// Mitsubishi GX Works2 project: PJT07_14_PLC(20220517_01)   PLC: Q03UDV

FUNCTION_BLOCK Alarm_FB
VAR_INPUT
  IB_Alarm : BOOL;  (* 入力@警報発生(0:-/1:発生) *)
END_VAR
VAR
  VT_AlarmDelayTimer : TIMER;  (* 内部@異常入力ﾃﾞｨﾚｲﾀｲﾏ *)
END_VAR
VAR_INPUT
  IW_DelayTimerVal : INT;  (* 入力@ﾃﾞｨﾚｲﾀｲﾏ値 *)
END_VAR
VAR_OUTPUT
  OB_AlarmHolding : BOOL;  (* 出力@ｱﾗｰﾑ自己保持(0:-/1:保持) *)
END_VAR
VAR_INPUT
  IB_AlarmResetPB : BOOL;  (* 入力@警報ﾘｾｯﾄPB(0:-/1:ﾘｾｯﾄ) *)
END_VAR
VAR
  VT_BuzzerStopTimer : TIMER;  (* 内部@ﾌﾞｻﾞｰｽﾄｯﾌﾟﾀｲﾏ *)
END_VAR
VAR_INPUT
  IW_BzStopTVal : INT;  (* 入力@ﾌﾞｻﾞｰｽﾄｯﾌﾟﾀｲﾏ値 *)
END_VAR
VAR
  VB_BuzzerStopFLG : BOOL;  (* 内部@ﾌﾞｻﾞｰｽﾄｯﾌﾟﾃﾞﾊﾞｲｽ(0:-/1:停止) *)
END_VAR
VAR_OUTPUT
  OB_DisplayFLG : BOOL;  (* 出力@ｱﾗｰﾑ表示ﾃﾞﾊﾞｲｽ(0:点滅/1:点灯) *)
END_VAR
VAR_INPUT
  IB_BuzzerStopPB : BOOL;  (* 入力@ﾌﾞｻﾞｰｽﾄｯﾌﾟPB(0:-/1:ｽﾄｯﾌﾟ) *)
END_VAR
VAR_OUTPUT
  OB_BuzzerFLG : BOOL;  (* 出力@ﾌﾞｻﾞｰﾌﾗｸﾞ *)
END_VAR
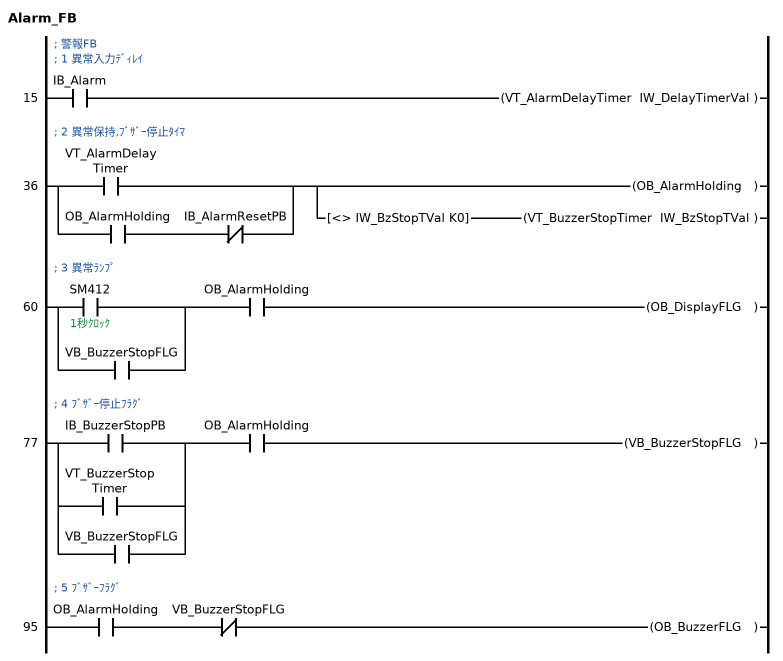
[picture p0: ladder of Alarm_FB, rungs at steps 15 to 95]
; 警報FB
; 1 異常入力ﾃﾞｨﾚｲ
15    LD      IB_Alarm
      OUT     VT_AlarmDelayTimer IW_DelayTimerVal
; 2 異常保持,ﾌﾞｻﾞｰ停止ﾀｲﾏ
36    LD      VT_AlarmDelayTimer
      LD      OB_AlarmHolding
      ANI     IB_AlarmResetPB
      ORB
      OUT     OB_AlarmHolding
      AND<>   IW_BzStopTVal K0
      OUT     VT_BuzzerStopTimer IW_BzStopTVal
; 3 異常ﾗﾝﾌﾟ
60    LD      SM412  ; 1秒ｸﾛｯｸ
      OR      VB_BuzzerStopFLG
      AND     OB_AlarmHolding
      OUT     OB_DisplayFLG
; 4 ﾌﾞｻﾞｰ停止ﾌﾗｸﾞ
77    LD      IB_BuzzerStopPB
      OR      VT_BuzzerStopTimer
      OR      VB_BuzzerStopFLG
      AND     OB_AlarmHolding
      OUT     VB_BuzzerStopFLG
; 5 ﾌﾞｻﾞｰﾌﾗｸﾞ
95    LD      OB_AlarmHolding
      ANI     VB_BuzzerStopFLG
      OUT     OB_BuzzerFLG
END_FUNCTION_BLOCK

PROGRAM 11_Alarm
VAR
  Alarm_FB_1 : Alarm_FB;
  Alarm_FB_2 : Alarm_FB;
END_VAR
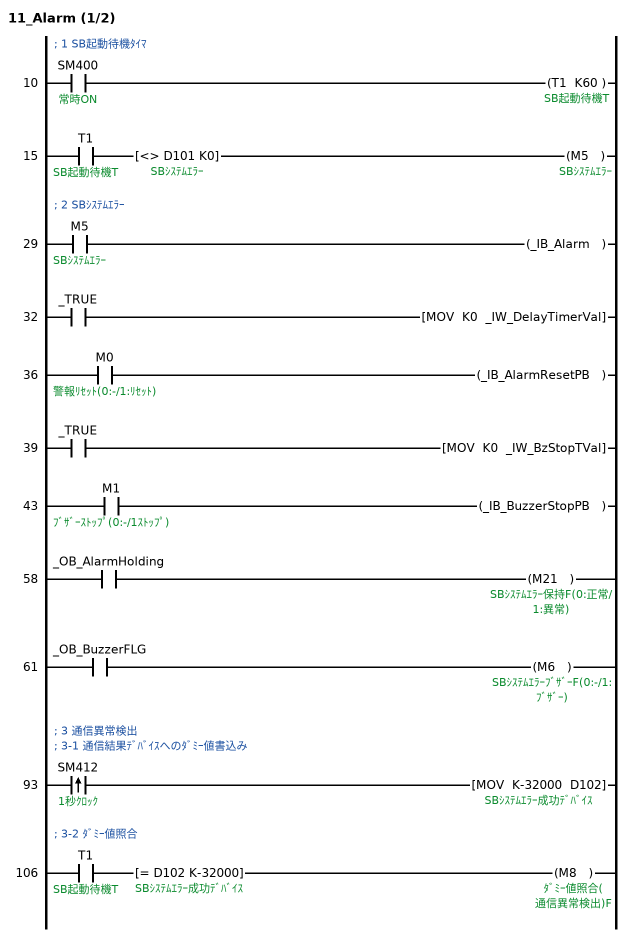
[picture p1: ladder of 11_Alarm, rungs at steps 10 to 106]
; 1 SB起動待機ﾀｲﾏ
10    LD      SM400  ; 常時ON
      OUT     T1 K60  ; SB起動待機T
15    LD      T1  ; SB起動待機T
      AND<>   D101 K0  ; SBｼｽﾃﾑｴﾗｰ
      OUT     M5  ; SBｼｽﾃﾑｴﾗｰ
; FB BLK START Alarm_FB(Alarm_FB_1)
; 2 SBｼｽﾃﾑｴﾗｰ
29    LD      M5  ; SBｼｽﾃﾑｴﾗｰ
      OUT     _IB_Alarm
32    LD      _TRUE
      MOV     K0 _IW_DelayTimerVal
36    LD      M0  ; 警報ﾘｾｯﾄ(0:-/1:ﾘｾｯﾄ)
      OUT     _IB_AlarmResetPB
39    LD      _TRUE
      MOV     K0 _IW_BzStopTVal
43    LD      M1  ; ﾌﾞｻﾞｰｽﾄｯﾌﾟ(0:-/1ｽﾄｯﾌﾟ)
      OUT     _IB_BuzzerStopPB
; FB START
; FB_NAME Alarm_FB
; INSTANCE_NAME Alarm_FB_1
; FB IN_B:IB_Alarm
; FB OUT_OB_AlarmHolding:B
; FB IN_W:IW_DelayTimerVal
; FB OUT_OB_DisplayFLG:B
; FB IN_B:IB_AlarmResetPB
; FB OUT_OB_BuzzerFLG:B
; FB IN_W:IW_BzStopTVal
; FB IN_B:IB_BuzzerStopPB
; FB END
58    LD      _OB_AlarmHolding
      OUT     M21  ; SBｼｽﾃﾑｴﾗｰ保持F(0:正常/1:異常)
61    LD      _OB_BuzzerFLG
      OUT     M6  ; SBｼｽﾃﾑｴﾗｰﾌﾞｻﾞｰF(0:-/1:ﾌﾞｻﾞｰ)
; FB BLK END
; 3 通信異常検出
; 3-1 通信結果ﾃﾞﾊﾞｲｽへのﾀﾞﾐｰ値書込み
93    LDP     SM412  ; 1秒ｸﾛｯｸ
      MOV     K-32000 D102  ; SBｼｽﾃﾑｴﾗｰ成功ﾃﾞﾊﾞｲｽ
; 3-2 ﾀﾞﾐｰ値照合
106   LD      T1  ; SB起動待機T
      AND=    D102 K-32000  ; SBｼｽﾃﾑｴﾗｰ成功ﾃﾞﾊﾞｲｽ
      OUT     M8  ; ﾀﾞﾐｰ値照合(通信異常検出)F
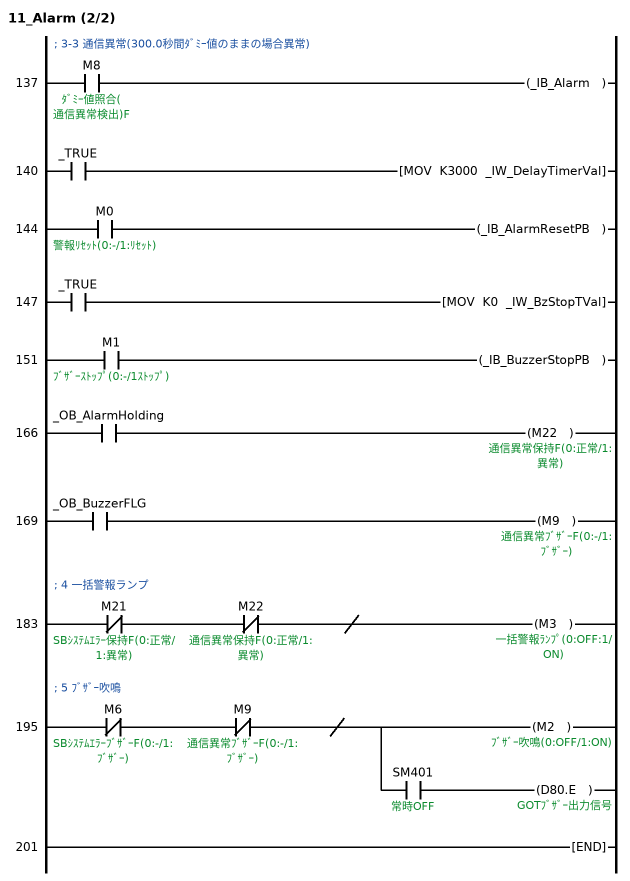
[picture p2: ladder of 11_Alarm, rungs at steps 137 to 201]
; FB BLK START Alarm_FB(Alarm_FB_2)
; 3-3 通信異常(300.0秒間ﾀﾞﾐｰ値のままの場合異常)
137   LD      M8  ; ﾀﾞﾐｰ値照合(通信異常検出)F
      OUT     _IB_Alarm
140   LD      _TRUE
      MOV     K3000 _IW_DelayTimerVal
144   LD      M0  ; 警報ﾘｾｯﾄ(0:-/1:ﾘｾｯﾄ)
      OUT     _IB_AlarmResetPB
147   LD      _TRUE
      MOV     K0 _IW_BzStopTVal
151   LD      M1  ; ﾌﾞｻﾞｰｽﾄｯﾌﾟ(0:-/1ｽﾄｯﾌﾟ)
      OUT     _IB_BuzzerStopPB
; FB START
; FB_NAME Alarm_FB
; INSTANCE_NAME Alarm_FB_2
; FB IN_B:IB_Alarm
; FB OUT_OB_AlarmHolding:B
; FB IN_W:IW_DelayTimerVal
; FB OUT_OB_DisplayFLG:B
; FB IN_B:IB_AlarmResetPB
; FB OUT_OB_BuzzerFLG:B
; FB IN_W:IW_BzStopTVal
; FB IN_B:IB_BuzzerStopPB
; FB END
166   LD      _OB_AlarmHolding
      OUT     M22  ; 通信異常保持F(0:正常/1:異常)
169   LD      _OB_BuzzerFLG
      OUT     M9  ; 通信異常ﾌﾞｻﾞｰF(0:-/1:ﾌﾞｻﾞｰ)
; FB BLK END
; 4 一括警報ランプ
183   LDI     M21  ; SBｼｽﾃﾑｴﾗｰ保持F(0:正常/1:異常)
      ANI     M22  ; 通信異常保持F(0:正常/1:異常)
      INV
      OUT     M3  ; 一括警報ﾗﾝﾌﾟ(0:OFF:1/ON)
; 5 ﾌﾞｻﾞｰ吹鳴
195   LDI     M6  ; SBｼｽﾃﾑｴﾗｰﾌﾞｻﾞｰF(0:-/1:ﾌﾞｻﾞｰ)
      ANI     M9  ; 通信異常ﾌﾞｻﾞｰF(0:-/1:ﾌﾞｻﾞｰ)
      INV
      OUT     M2  ; ﾌﾞｻﾞｰ吹鳴(0:OFF/1:ON)
      AND     SM401  ; 常時OFF
      OUT     D80.E  ; GOTﾌﾞｻﾞｰ出力信号
201   END
END_PROGRAM

PROGRAM 02_#2  // SB_Initial
VAR
  __IST_553ac48fffaf4984 : I+ST_553ac48fffaf4984;
END_VAR
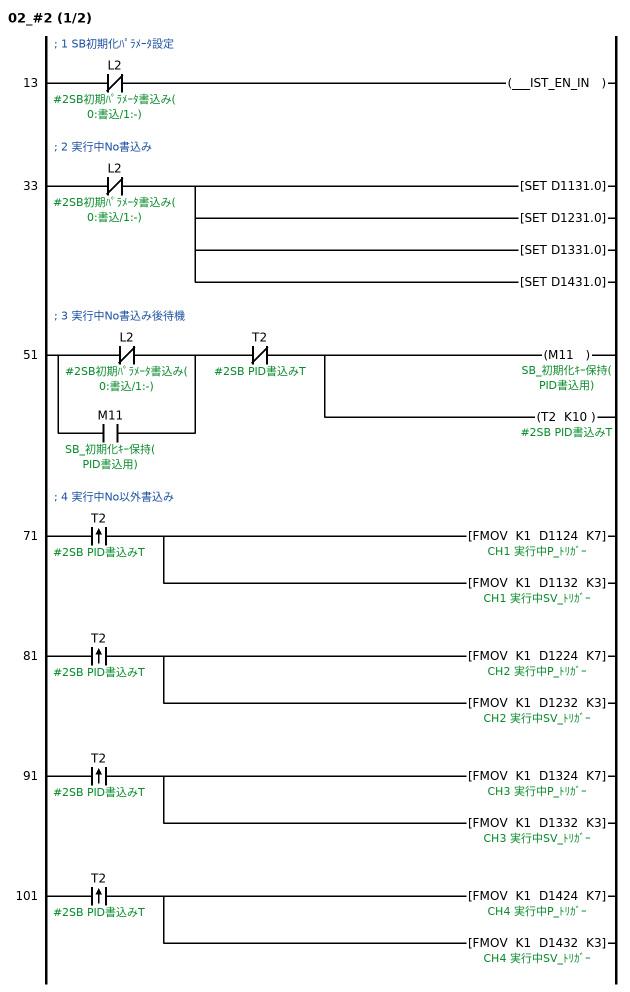
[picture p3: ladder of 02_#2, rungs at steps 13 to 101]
; FB BLK START I+ST_553ac48fffaf4984(__IST_553ac48fffaf4984)
; 1 SB初期化ﾊﾟﾗﾒｰﾀ設定
13    LDI     L2  ; #2SB初期ﾊﾟﾗﾒｰﾀ書込み(0:書込/1:-)
      OUT     ___IST_EN_IN
; FB START
; FB_NAME I+ST_553ac48fffaf4984
; INSTANCE_NAME __IST_553ac48fffaf4984
; FB IN_B:__IST_EN_IN
; FB OUT___IST_EN_OUT:B
; FB END
; FB BLK END
; 2 実行中No書込み
33    LDI     L2  ; #2SB初期ﾊﾟﾗﾒｰﾀ書込み(0:書込/1:-)
      SET     D1131.0
      SET     D1231.0
      SET     D1331.0
      SET     D1431.0
; 3 実行中No書込み後待機
51    LDI     L2  ; #2SB初期ﾊﾟﾗﾒｰﾀ書込み(0:書込/1:-)
      OR      M11  ; SB_初期化ｷｰ保持(PID書込用)
      ANI     T2  ; #2SB PID書込みT
      OUT     M11  ; SB_初期化ｷｰ保持(PID書込用)
      OUT     T2 K10  ; #2SB PID書込みT
; 4 実行中No以外書込み
71    LDP     T2  ; #2SB PID書込みT
      FMOV    K1 D1124 K7  ; CH1 実行中P_ﾄﾘｶﾞｰ
      FMOV    K1 D1132 K3  ; CH1 実行中SV_ﾄﾘｶﾞｰ
81    LDP     T2  ; #2SB PID書込みT
      FMOV    K1 D1224 K7  ; CH2 実行中P_ﾄﾘｶﾞｰ
      FMOV    K1 D1232 K3  ; CH2 実行中SV_ﾄﾘｶﾞｰ
91    LDP     T2  ; #2SB PID書込みT
      FMOV    K1 D1324 K7  ; CH3 実行中P_ﾄﾘｶﾞｰ
      FMOV    K1 D1332 K3  ; CH3 実行中SV_ﾄﾘｶﾞｰ
101   LDP     T2  ; #2SB PID書込みT
      FMOV    K1 D1424 K7  ; CH4 実行中P_ﾄﾘｶﾞｰ
      FMOV    K1 D1432 K3  ; CH4 実行中SV_ﾄﾘｶﾞｰ
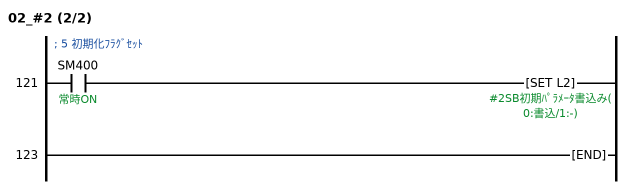
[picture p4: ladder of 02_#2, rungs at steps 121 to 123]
; 5 初期化ﾌﾗｸﾞｾｯﾄ
121   LD      SM400  ; 常時ON
      SET     L2  ; #2SB初期ﾊﾟﾗﾒｰﾀ書込み(0:書込/1:-)
123   END
END_PROGRAM

PROGRAM 22_#2  // SB100
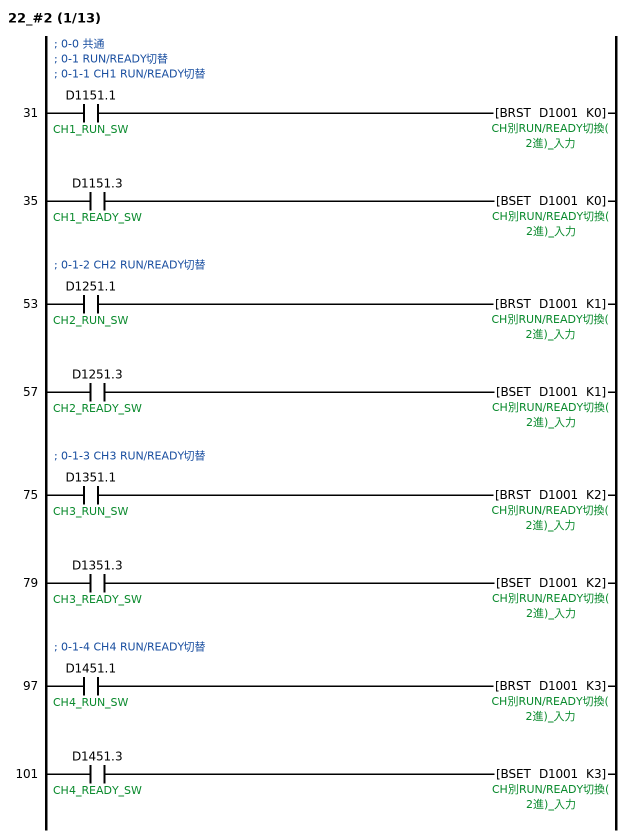
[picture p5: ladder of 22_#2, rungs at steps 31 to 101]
; 0-0 共通
; 0-1 RUN/READY切替
; 0-1-1 CH1 RUN/READY切替
31    LD      D1151.1  ; CH1_RUN_SW
      BRST    D1001 K0  ; CH別RUN/READY切換(2進)_入力
35    LD      D1151.3  ; CH1_READY_SW
      BSET    D1001 K0
; 0-1-2 CH2 RUN/READY切替
53    LD      D1251.1  ; CH2_RUN_SW
      BRST    D1001 K1
57    LD      D1251.3  ; CH2_READY_SW
      BSET    D1001 K1
; 0-1-3 CH3 RUN/READY切替
75    LD      D1351.1  ; CH3_RUN_SW
      BRST    D1001 K2
79    LD      D1351.3  ; CH3_READY_SW
      BSET    D1001 K2
; 0-1-4 CH4 RUN/READY切替
97    LD      D1451.1  ; CH4_RUN_SW
      BRST    D1001 K3
101   LD      D1451.3  ; CH4_READY_SW
      BSET    D1001 K3
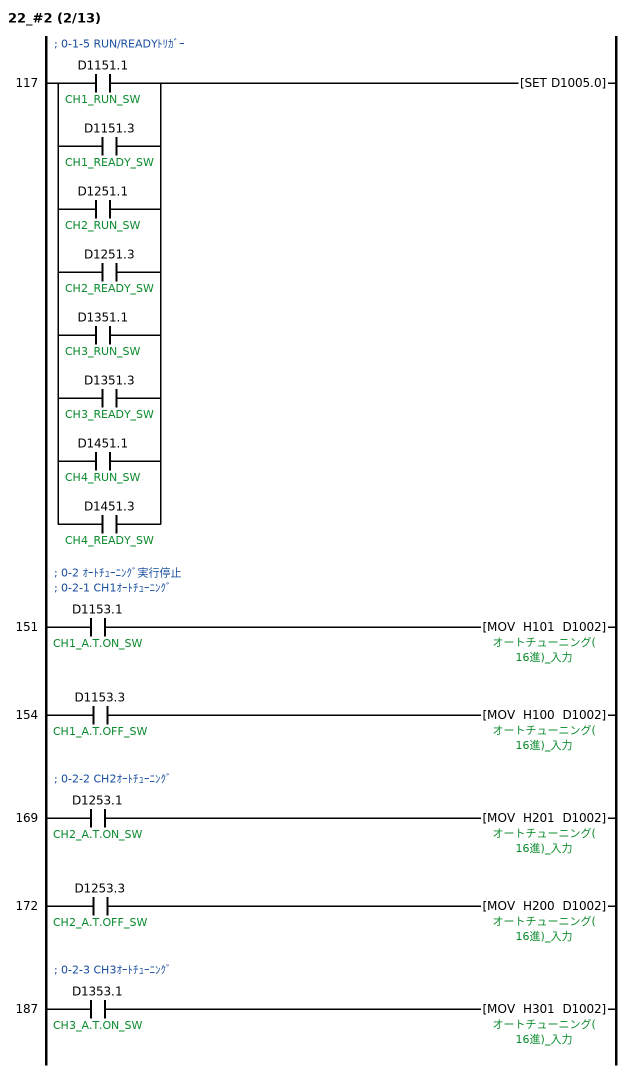
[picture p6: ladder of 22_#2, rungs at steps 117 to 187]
; 0-1-5 RUN/READYﾄﾘｶﾞｰ
117   LD      D1151.1  ; CH1_RUN_SW
      OR      D1151.3  ; CH1_READY_SW
      OR      D1251.1  ; CH2_RUN_SW
      OR      D1251.3  ; CH2_READY_SW
      OR      D1351.1  ; CH3_RUN_SW
      OR      D1351.3  ; CH3_READY_SW
      OR      D1451.1  ; CH4_RUN_SW
      OR      D1451.3  ; CH4_READY_SW
      SET     D1005.0
; 0-2 ｵｰﾄﾁｭｰﾆﾝｸﾞ実行停止
; 0-2-1 CH1ｵｰﾄﾁｭｰﾆﾝｸﾞ
151   LD      D1153.1  ; CH1_A.T.ON_SW
      MOV     H101 D1002  ; オートチューニング(16進)_入力
154   LD      D1153.3  ; CH1_A.T.OFF_SW
      MOV     H100 D1002
; 0-2-2 CH2ｵｰﾄﾁｭｰﾆﾝｸﾞ
169   LD      D1253.1  ; CH2_A.T.ON_SW
      MOV     H201 D1002
172   LD      D1253.3  ; CH2_A.T.OFF_SW
      MOV     H200 D1002
; 0-2-3 CH3ｵｰﾄﾁｭｰﾆﾝｸﾞ
187   LD      D1353.1  ; CH3_A.T.ON_SW
      MOV     H301 D1002
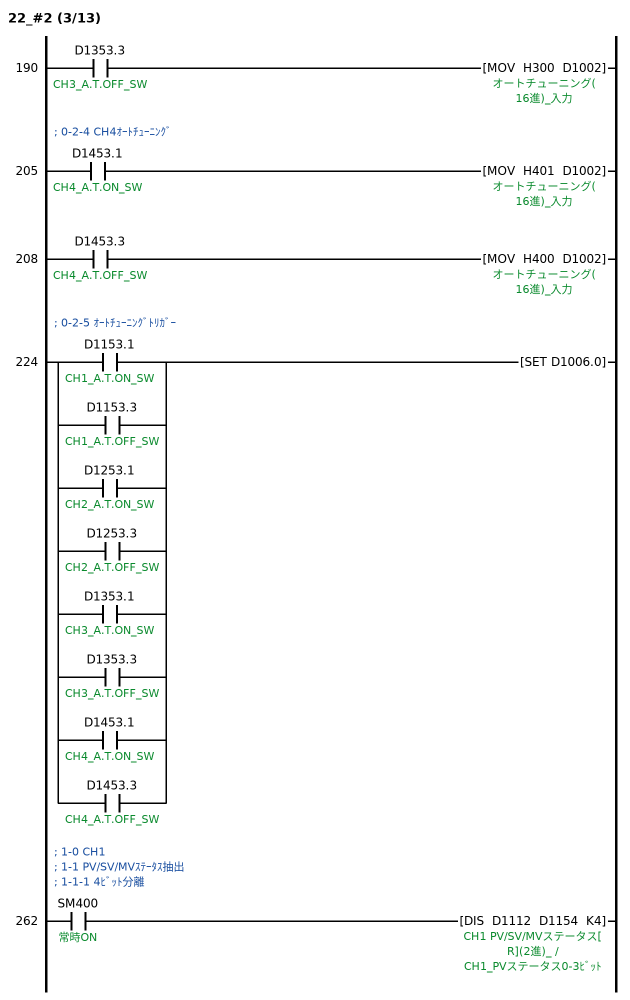
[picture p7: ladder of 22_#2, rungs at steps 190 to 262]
190   LD      D1353.3  ; CH3_A.T.OFF_SW
      MOV     H300 D1002
; 0-2-4 CH4ｵｰﾄﾁｭｰﾆﾝｸﾞ
205   LD      D1453.1  ; CH4_A.T.ON_SW
      MOV     H401 D1002
208   LD      D1453.3  ; CH4_A.T.OFF_SW
      MOV     H400 D1002
; 0-2-5 ｵｰﾄﾁｭｰﾆﾝｸﾞﾄﾘｶﾞｰ
224   LD      D1153.1  ; CH1_A.T.ON_SW
      OR      D1153.3  ; CH1_A.T.OFF_SW
      OR      D1253.1  ; CH2_A.T.ON_SW
      OR      D1253.3  ; CH2_A.T.OFF_SW
      OR      D1353.1  ; CH3_A.T.ON_SW
      OR      D1353.3  ; CH3_A.T.OFF_SW
      OR      D1453.1  ; CH4_A.T.ON_SW
      OR      D1453.3  ; CH4_A.T.OFF_SW
      SET     D1006.0
; 1-0 CH1
; 1-1 PV/SV/MVｽﾃｰﾀｽ抽出
; 1-1-1 4ﾋﾞｯﾄ分離
262   LD      SM400  ; 常時ON
      DIS     D1112 D1154 K4  ; CH1 PV/SV/MVステータス[R](2進)_ / CH1_PVステータス0-3ﾋﾞｯﾄ
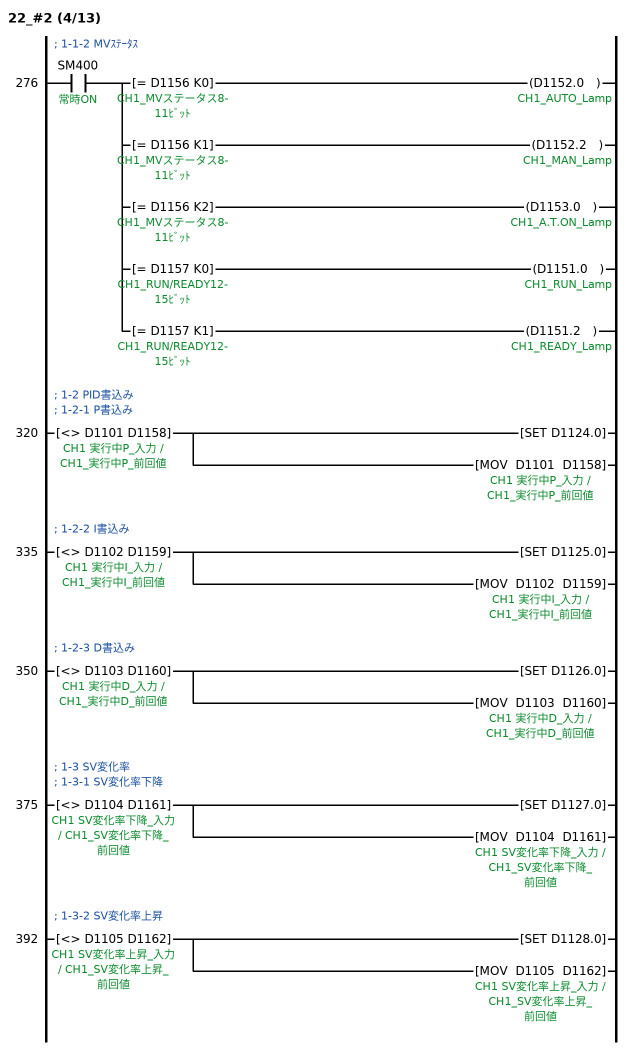
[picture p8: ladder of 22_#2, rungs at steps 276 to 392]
; 1-1-2 MVｽﾃｰﾀｽ
276   LD      SM400  ; 常時ON
      MPS
      AND=    D1156 K0  ; CH1_MVステータス8-11ﾋﾞｯﾄ
      OUT     D1152.0  ; CH1_AUTO_Lamp
      MRD
      AND=    D1156 K1  ; CH1_MVステータス8-11ﾋﾞｯﾄ
      OUT     D1152.2  ; CH1_MAN_Lamp
      MRD
      AND=    D1156 K2  ; CH1_MVステータス8-11ﾋﾞｯﾄ
      OUT     D1153.0  ; CH1_A.T.ON_Lamp
      MRD
      AND=    D1157 K0  ; CH1_RUN/READY12-15ﾋﾞｯﾄ
      OUT     D1151.0  ; CH1_RUN_Lamp
      MPP
      AND=    D1157 K1  ; CH1_RUN/READY12-15ﾋﾞｯﾄ
      OUT     D1151.2  ; CH1_READY_Lamp
; 1-2 PID書込み
; 1-2-1 P書込み
320   LD<>    D1101 D1158  ; CH1 実行中P_入力 / CH1_実行中P_前回値
      SET     D1124.0
      MOV     D1101 D1158
; 1-2-2 I書込み
335   LD<>    D1102 D1159  ; CH1 実行中I_入力 / CH1_実行中I_前回値
      SET     D1125.0
      MOV     D1102 D1159
; 1-2-3 D書込み
350   LD<>    D1103 D1160  ; CH1 実行中D_入力 / CH1_実行中D_前回値
      SET     D1126.0
      MOV     D1103 D1160
; 1-3 SV変化率
; 1-3-1 SV変化率下降
375   LD<>    D1104 D1161  ; CH1 SV変化率下降_入力 / CH1_SV変化率下降_前回値
      SET     D1127.0
      MOV     D1104 D1161
; 1-3-2 SV変化率上昇
392   LD<>    D1105 D1162  ; CH1 SV変化率上昇_入力 / CH1_SV変化率上昇_前回値
      SET     D1128.0
      MOV     D1105 D1162
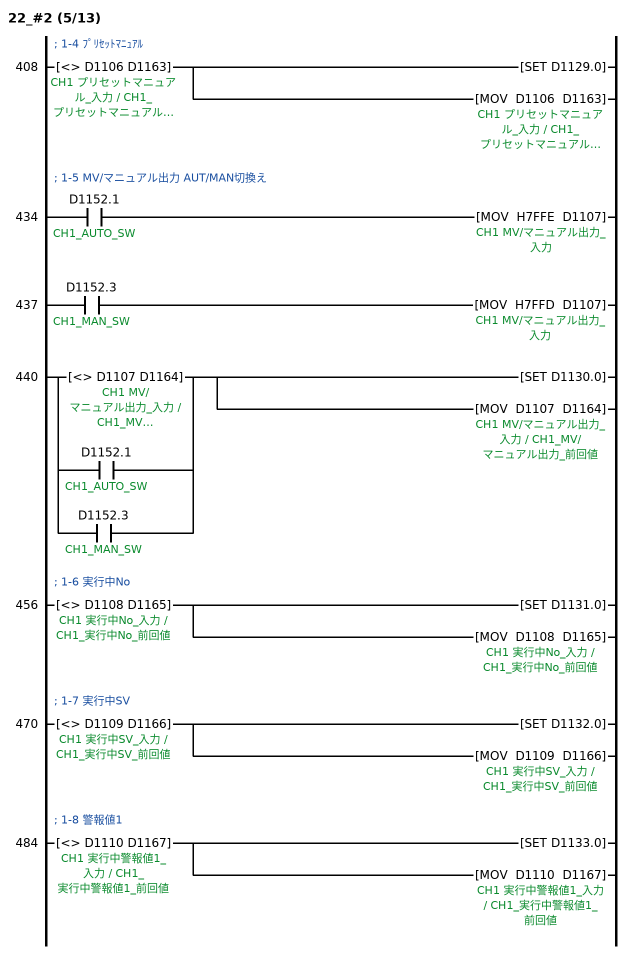
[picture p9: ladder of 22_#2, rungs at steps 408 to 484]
; 1-4 ﾌﾟﾘｾｯﾄﾏﾆｭｱﾙ
408   LD<>    D1106 D1163  ; CH1 プリセットマニュアル_入力 / CH1_プリセットマニュアル_前回値
      SET     D1129.0
      MOV     D1106 D1163
; 1-5 MV/マニュアル出力 AUT/MAN切換え
434   LD      D1152.1  ; CH1_AUTO_SW
      MOV     H7FFE D1107  ; CH1 MV/マニュアル出力_入力
437   LD      D1152.3  ; CH1_MAN_SW
      MOV     H7FFD D1107
440   LD<>    D1107 D1164  ; CH1 MV/マニュアル出力_入力 / CH1_MV/マニュアル出力_前回値
      OR      D1152.1  ; CH1_AUTO_SW
      OR      D1152.3  ; CH1_MAN_SW
      SET     D1130.0
      MOV     D1107 D1164
; 1-6 実行中No
456   LD<>    D1108 D1165  ; CH1 実行中No_入力 / CH1_実行中No_前回値
      SET     D1131.0
      MOV     D1108 D1165
; 1-7 実行中SV
470   LD<>    D1109 D1166  ; CH1 実行中SV_入力 / CH1_実行中SV_前回値
      SET     D1132.0
      MOV     D1109 D1166
; 1-8 警報値1
484   LD<>    D1110 D1167  ; CH1 実行中警報値1_入力 / CH1_実行中警報値1_前回値
      SET     D1133.0
      MOV     D1110 D1167
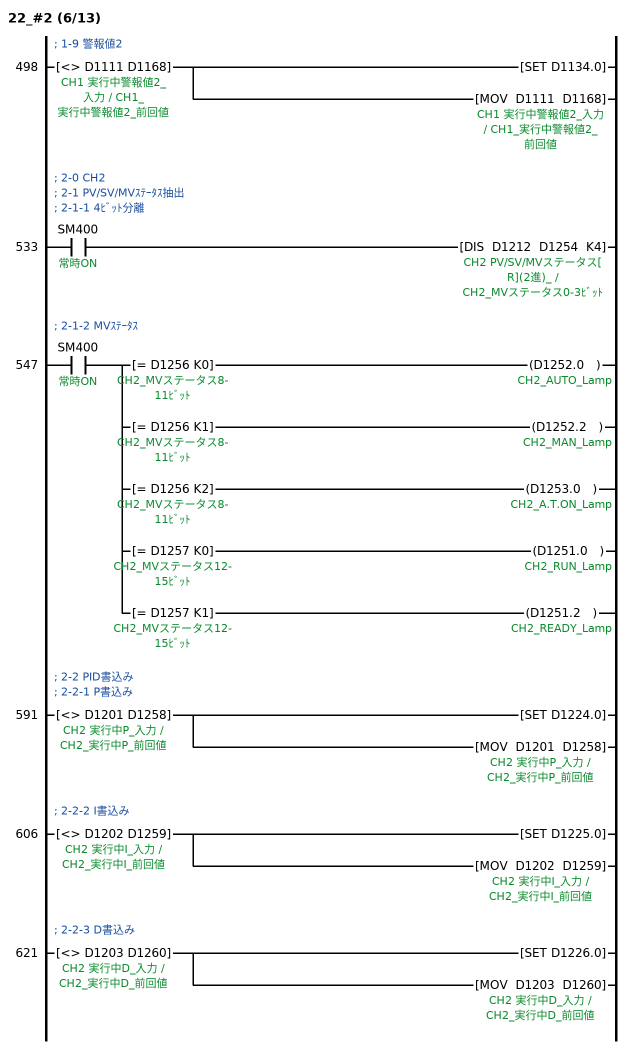
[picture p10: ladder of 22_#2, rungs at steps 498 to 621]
; 1-9 警報値2
498   LD<>    D1111 D1168  ; CH1 実行中警報値2_入力 / CH1_実行中警報値2_前回値
      SET     D1134.0
      MOV     D1111 D1168
; 2-0 CH2
; 2-1 PV/SV/MVｽﾃｰﾀｽ抽出
; 2-1-1 4ﾋﾞｯﾄ分離
533   LD      SM400  ; 常時ON
      DIS     D1212 D1254 K4  ; CH2 PV/SV/MVステータス[R](2進)_ / CH2_MVステータス0-3ﾋﾞｯﾄ
; 2-1-2 MVｽﾃｰﾀｽ
547   LD      SM400  ; 常時ON
      MPS
      AND=    D1256 K0  ; CH2_MVステータス8-11ﾋﾞｯﾄ
      OUT     D1252.0  ; CH2_AUTO_Lamp
      MRD
      AND=    D1256 K1  ; CH2_MVステータス8-11ﾋﾞｯﾄ
      OUT     D1252.2  ; CH2_MAN_Lamp
      MRD
      AND=    D1256 K2  ; CH2_MVステータス8-11ﾋﾞｯﾄ
      OUT     D1253.0  ; CH2_A.T.ON_Lamp
      MRD
      AND=    D1257 K0  ; CH2_MVステータス12-15ﾋﾞｯﾄ
      OUT     D1251.0  ; CH2_RUN_Lamp
      MPP
      AND=    D1257 K1  ; CH2_MVステータス12-15ﾋﾞｯﾄ
      OUT     D1251.2  ; CH2_READY_Lamp
; 2-2 PID書込み
; 2-2-1 P書込み
591   LD<>    D1201 D1258  ; CH2 実行中P_入力 / CH2_実行中P_前回値
      SET     D1224.0
      MOV     D1201 D1258
; 2-2-2 I書込み
606   LD<>    D1202 D1259  ; CH2 実行中I_入力 / CH2_実行中I_前回値
      SET     D1225.0
      MOV     D1202 D1259
; 2-2-3 D書込み
621   LD<>    D1203 D1260  ; CH2 実行中D_入力 / CH2_実行中D_前回値
      SET     D1226.0
      MOV     D1203 D1260
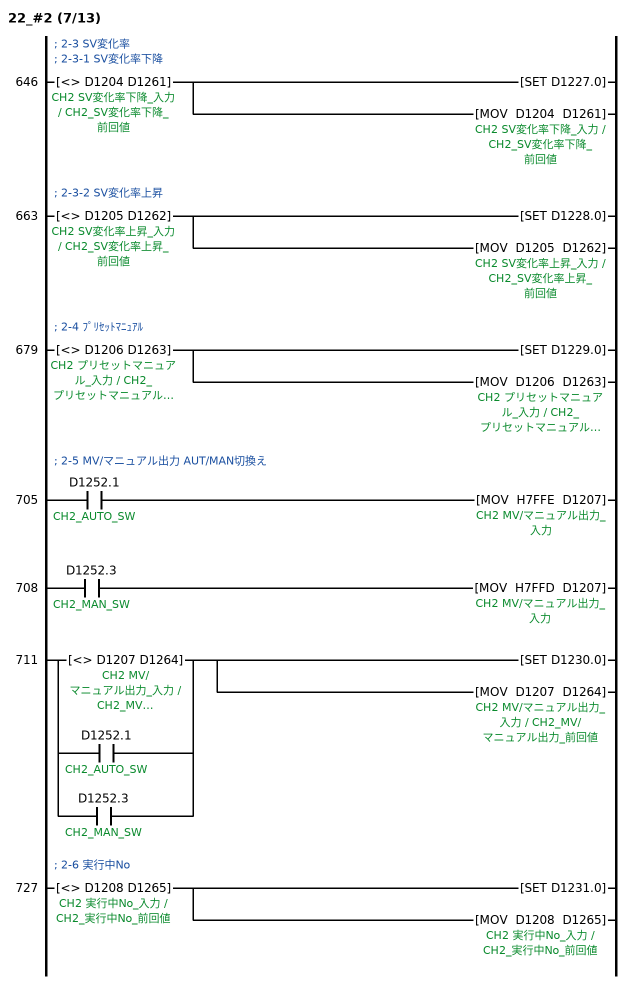
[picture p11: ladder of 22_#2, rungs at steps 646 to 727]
; 2-3 SV変化率
; 2-3-1 SV変化率下降
646   LD<>    D1204 D1261  ; CH2 SV変化率下降_入力 / CH2_SV変化率下降_前回値
      SET     D1227.0
      MOV     D1204 D1261
; 2-3-2 SV変化率上昇
663   LD<>    D1205 D1262  ; CH2 SV変化率上昇_入力 / CH2_SV変化率上昇_前回値
      SET     D1228.0
      MOV     D1205 D1262
; 2-4 ﾌﾟﾘｾｯﾄﾏﾆｭｱﾙ
679   LD<>    D1206 D1263  ; CH2 プリセットマニュアル_入力 / CH2_プリセットマニュアル_前回値
      SET     D1229.0
      MOV     D1206 D1263
; 2-5 MV/マニュアル出力 AUT/MAN切換え
705   LD      D1252.1  ; CH2_AUTO_SW
      MOV     H7FFE D1207  ; CH2 MV/マニュアル出力_入力
708   LD      D1252.3  ; CH2_MAN_SW
      MOV     H7FFD D1207
711   LD<>    D1207 D1264  ; CH2 MV/マニュアル出力_入力 / CH2_MV/マニュアル出力_前回値
      OR      D1252.1  ; CH2_AUTO_SW
      OR      D1252.3  ; CH2_MAN_SW
      SET     D1230.0
      MOV     D1207 D1264
; 2-6 実行中No
727   LD<>    D1208 D1265  ; CH2 実行中No_入力 / CH2_実行中No_前回値
      SET     D1231.0
      MOV     D1208 D1265
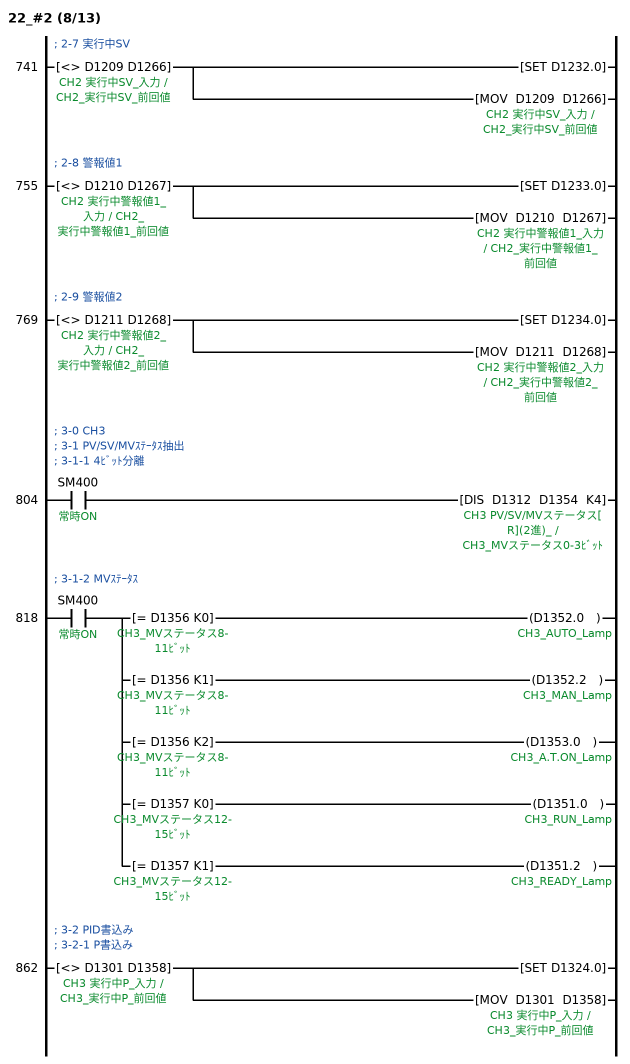
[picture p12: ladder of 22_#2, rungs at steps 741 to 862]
; 2-7 実行中SV
741   LD<>    D1209 D1266  ; CH2 実行中SV_入力 / CH2_実行中SV_前回値
      SET     D1232.0
      MOV     D1209 D1266
; 2-8 警報値1
755   LD<>    D1210 D1267  ; CH2 実行中警報値1_入力 / CH2_実行中警報値1_前回値
      SET     D1233.0
      MOV     D1210 D1267
; 2-9 警報値2
769   LD<>    D1211 D1268  ; CH2 実行中警報値2_入力 / CH2_実行中警報値2_前回値
      SET     D1234.0
      MOV     D1211 D1268
; 3-0 CH3
; 3-1 PV/SV/MVｽﾃｰﾀｽ抽出
; 3-1-1 4ﾋﾞｯﾄ分離
804   LD      SM400  ; 常時ON
      DIS     D1312 D1354 K4  ; CH3 PV/SV/MVステータス[R](2進)_ / CH3_MVステータス0-3ﾋﾞｯﾄ
; 3-1-2 MVｽﾃｰﾀｽ
818   LD      SM400  ; 常時ON
      MPS
      AND=    D1356 K0  ; CH3_MVステータス8-11ﾋﾞｯﾄ
      OUT     D1352.0  ; CH3_AUTO_Lamp
      MRD
      AND=    D1356 K1  ; CH3_MVステータス8-11ﾋﾞｯﾄ
      OUT     D1352.2  ; CH3_MAN_Lamp
      MRD
      AND=    D1356 K2  ; CH3_MVステータス8-11ﾋﾞｯﾄ
      OUT     D1353.0  ; CH3_A.T.ON_Lamp
      MRD
      AND=    D1357 K0  ; CH3_MVステータス12-15ﾋﾞｯﾄ
      OUT     D1351.0  ; CH3_RUN_Lamp
      MPP
      AND=    D1357 K1  ; CH3_MVステータス12-15ﾋﾞｯﾄ
      OUT     D1351.2  ; CH3_READY_Lamp
; 3-2 PID書込み
; 3-2-1 P書込み
862   LD<>    D1301 D1358  ; CH3 実行中P_入力 / CH3_実行中P_前回値
      SET     D1324.0
      MOV     D1301 D1358
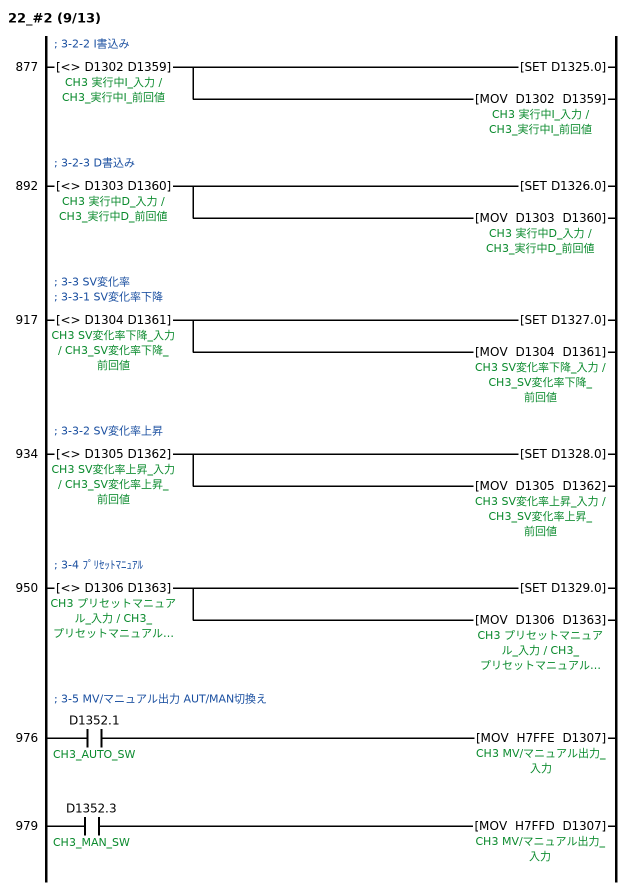
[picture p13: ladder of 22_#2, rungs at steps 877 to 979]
; 3-2-2 I書込み
877   LD<>    D1302 D1359  ; CH3 実行中I_入力 / CH3_実行中I_前回値
      SET     D1325.0
      MOV     D1302 D1359
; 3-2-3 D書込み
892   LD<>    D1303 D1360  ; CH3 実行中D_入力 / CH3_実行中D_前回値
      SET     D1326.0
      MOV     D1303 D1360
; 3-3 SV変化率
; 3-3-1 SV変化率下降
917   LD<>    D1304 D1361  ; CH3 SV変化率下降_入力 / CH3_SV変化率下降_前回値
      SET     D1327.0
      MOV     D1304 D1361
; 3-3-2 SV変化率上昇
934   LD<>    D1305 D1362  ; CH3 SV変化率上昇_入力 / CH3_SV変化率上昇_前回値
      SET     D1328.0
      MOV     D1305 D1362
; 3-4 ﾌﾟﾘｾｯﾄﾏﾆｭｱﾙ
950   LD<>    D1306 D1363  ; CH3 プリセットマニュアル_入力 / CH3_プリセットマニュアル_前回値
      SET     D1329.0
      MOV     D1306 D1363
; 3-5 MV/マニュアル出力 AUT/MAN切換え
976   LD      D1352.1  ; CH3_AUTO_SW
      MOV     H7FFE D1307  ; CH3 MV/マニュアル出力_入力
979   LD      D1352.3  ; CH3_MAN_SW
      MOV     H7FFD D1307
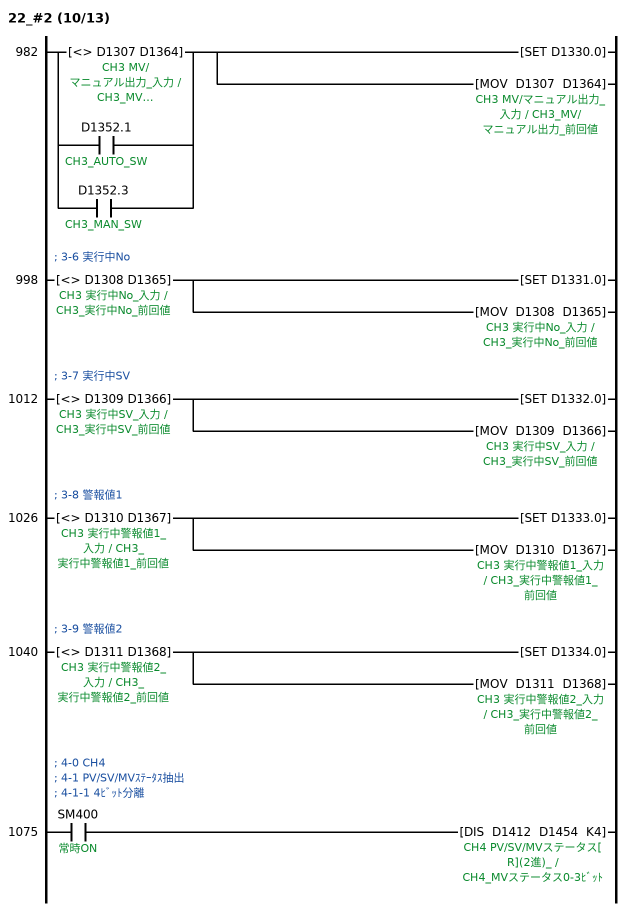
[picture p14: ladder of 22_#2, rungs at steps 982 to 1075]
982   LD<>    D1307 D1364  ; CH3 MV/マニュアル出力_入力 / CH3_MV/マニュアル出力_前回値
      OR      D1352.1  ; CH3_AUTO_SW
      OR      D1352.3  ; CH3_MAN_SW
      SET     D1330.0
      MOV     D1307 D1364
; 3-6 実行中No
998   LD<>    D1308 D1365  ; CH3 実行中No_入力 / CH3_実行中No_前回値
      SET     D1331.0
      MOV     D1308 D1365
; 3-7 実行中SV
1012  LD<>    D1309 D1366  ; CH3 実行中SV_入力 / CH3_実行中SV_前回値
      SET     D1332.0
      MOV     D1309 D1366
; 3-8 警報値1
1026  LD<>    D1310 D1367  ; CH3 実行中警報値1_入力 / CH3_実行中警報値1_前回値
      SET     D1333.0
      MOV     D1310 D1367
; 3-9 警報値2
1040  LD<>    D1311 D1368  ; CH3 実行中警報値2_入力 / CH3_実行中警報値2_前回値
      SET     D1334.0
      MOV     D1311 D1368
; 4-0 CH4
; 4-1 PV/SV/MVｽﾃｰﾀｽ抽出
; 4-1-1 4ﾋﾞｯﾄ分離
1075  LD      SM400  ; 常時ON
      DIS     D1412 D1454 K4  ; CH4 PV/SV/MVステータス[R](2進)_ / CH4_MVステータス0-3ﾋﾞｯﾄ
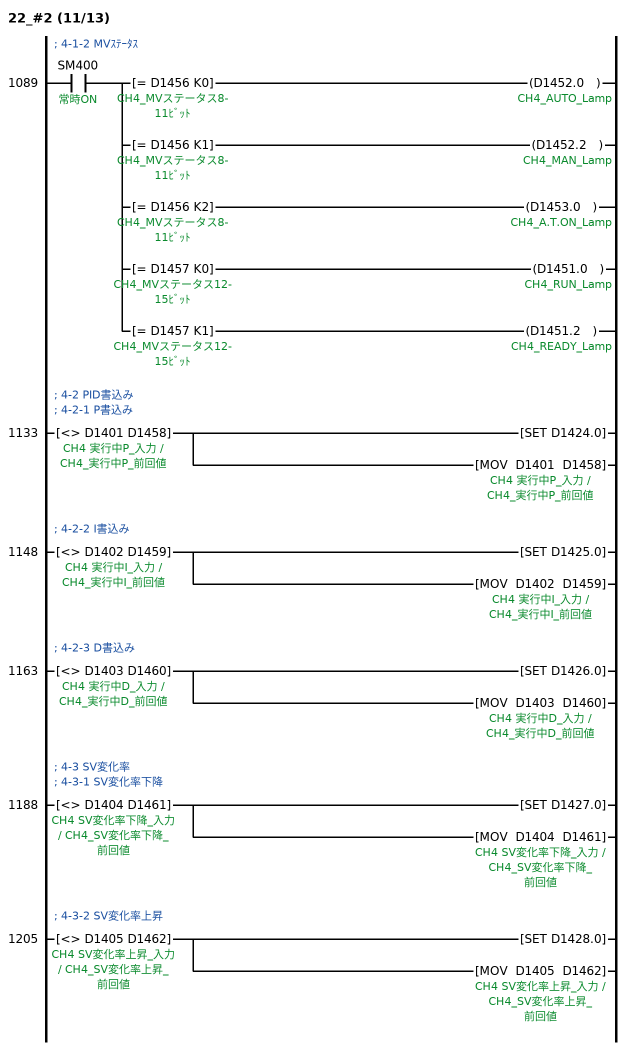
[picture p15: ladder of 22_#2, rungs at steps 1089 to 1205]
; 4-1-2 MVｽﾃｰﾀｽ
1089  LD      SM400  ; 常時ON
      MPS
      AND=    D1456 K0  ; CH4_MVステータス8-11ﾋﾞｯﾄ
      OUT     D1452.0  ; CH4_AUTO_Lamp
      MRD
      AND=    D1456 K1  ; CH4_MVステータス8-11ﾋﾞｯﾄ
      OUT     D1452.2  ; CH4_MAN_Lamp
      MRD
      AND=    D1456 K2  ; CH4_MVステータス8-11ﾋﾞｯﾄ
      OUT     D1453.0  ; CH4_A.T.ON_Lamp
      MRD
      AND=    D1457 K0  ; CH4_MVステータス12-15ﾋﾞｯﾄ
      OUT     D1451.0  ; CH4_RUN_Lamp
      MPP
      AND=    D1457 K1  ; CH4_MVステータス12-15ﾋﾞｯﾄ
      OUT     D1451.2  ; CH4_READY_Lamp
; 4-2 PID書込み
; 4-2-1 P書込み
1133  LD<>    D1401 D1458  ; CH4 実行中P_入力 / CH4_実行中P_前回値
      SET     D1424.0
      MOV     D1401 D1458
; 4-2-2 I書込み
1148  LD<>    D1402 D1459  ; CH4 実行中I_入力 / CH4_実行中I_前回値
      SET     D1425.0
      MOV     D1402 D1459
; 4-2-3 D書込み
1163  LD<>    D1403 D1460  ; CH4 実行中D_入力 / CH4_実行中D_前回値
      SET     D1426.0
      MOV     D1403 D1460
; 4-3 SV変化率
; 4-3-1 SV変化率下降
1188  LD<>    D1404 D1461  ; CH4 SV変化率下降_入力 / CH4_SV変化率下降_前回値
      SET     D1427.0
      MOV     D1404 D1461
; 4-3-2 SV変化率上昇
1205  LD<>    D1405 D1462  ; CH4 SV変化率上昇_入力 / CH4_SV変化率上昇_前回値
      SET     D1428.0
      MOV     D1405 D1462
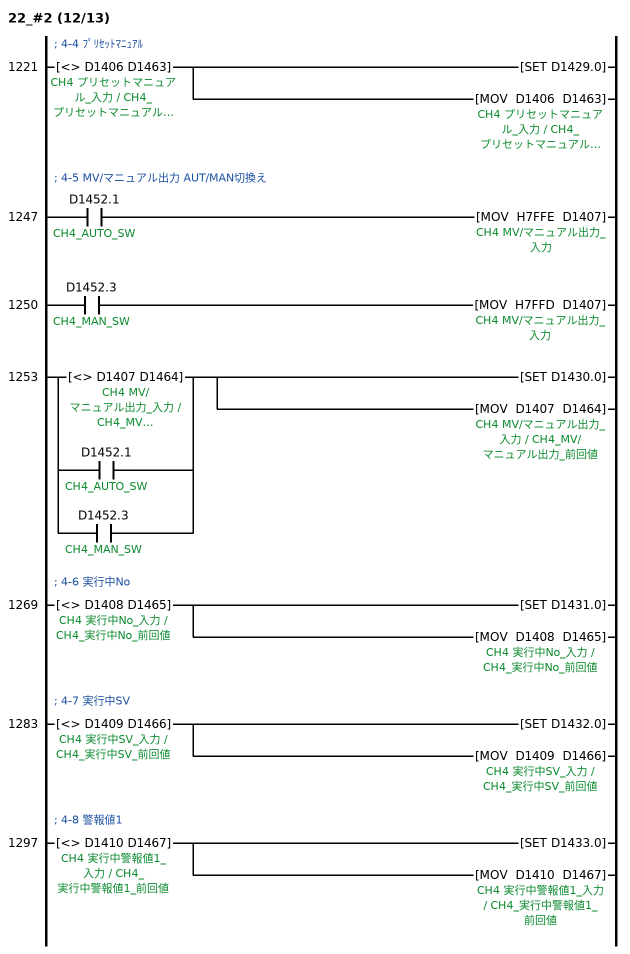
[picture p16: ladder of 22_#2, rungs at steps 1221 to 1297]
; 4-4 ﾌﾟﾘｾｯﾄﾏﾆｭｱﾙ
1221  LD<>    D1406 D1463  ; CH4 プリセットマニュアル_入力 / CH4_プリセットマニュアル_前回値
      SET     D1429.0
      MOV     D1406 D1463
; 4-5 MV/マニュアル出力 AUT/MAN切換え
1247  LD      D1452.1  ; CH4_AUTO_SW
      MOV     H7FFE D1407  ; CH4 MV/マニュアル出力_入力
1250  LD      D1452.3  ; CH4_MAN_SW
      MOV     H7FFD D1407
1253  LD<>    D1407 D1464  ; CH4 MV/マニュアル出力_入力 / CH4_MV/マニュアル出力_前回値
      OR      D1452.1  ; CH4_AUTO_SW
      OR      D1452.3  ; CH4_MAN_SW
      SET     D1430.0
      MOV     D1407 D1464
; 4-6 実行中No
1269  LD<>    D1408 D1465  ; CH4 実行中No_入力 / CH4_実行中No_前回値
      SET     D1431.0
      MOV     D1408 D1465
; 4-7 実行中SV
1283  LD<>    D1409 D1466  ; CH4 実行中SV_入力 / CH4_実行中SV_前回値
      SET     D1432.0
      MOV     D1409 D1466
; 4-8 警報値1
1297  LD<>    D1410 D1467  ; CH4 実行中警報値1_入力 / CH4_実行中警報値1_前回値
      SET     D1433.0
      MOV     D1410 D1467
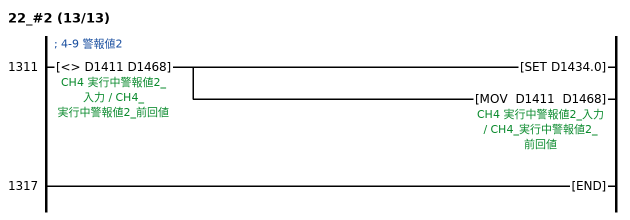
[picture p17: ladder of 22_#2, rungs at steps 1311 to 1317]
; 4-9 警報値2
1311  LD<>    D1411 D1468  ; CH4 実行中警報値2_入力 / CH4_実行中警報値2_前回値
      SET     D1434.0
      MOV     D1411 D1468
1317  END
END_PROGRAM

FUNCTION_BLOCK I+ST_553ac48fffaf4984
VAR_INPUT
  __IST_EN_IN : BOOL;
END_VAR
VAR_OUTPUT
  __IST_EN_OUT : BOOL;
END_VAR
(* IST HEADER START *)
IF NOT __IST_EN_IN THEN __IST_EN_OUT:=FALSE; RETURN; END_IF;
(* VERSION=1:TYPE=STB *)
(* IST HEADER END *)
D1101:=50;		(*CH1 実行中P*)
D1102:=60;		(*CH1 実行中I*)
D1103:=30;		(*CH1 実行中D*)
D1104:=0;		(*CH1 SV変化率下降*)
D1105:=0;		(*CH1 SV変化率上昇*)
D1106:=0;		(*CH1 プリセットマニュアル*)
D1108:=1;		(*CH1 実行中No*)
D1109:=234;		(*CH1 実行中SV*)
D1110:=30000;	(*CH1 実行中警報値1*)
D1111:=-30000;	(*CH1 実行中警報値2*)
D1201:=50;		(*CH2 実行中P*)
D1202:=60;		(*CH2 実行中I*)
D1203:=30;		(*CH2 実行中D*)
D1204:=0;		(*CH2 SV変化率下降*)
D1205:=0;		(*CH2 SV変化率上昇*)
D1206:=0;		(*CH2 プリセットマニュアル*)
D1208:=1;		(*CH2 実行中No*)
D1209:=234;		(*CH2 実行中SV*)
D1210:=30000;	(*CH2 実行中警報値1*)
D1211:=-30000;	(*CH2 実行中警報値2*)
D1301:=50;		(*CH3 実行中P*)
D1302:=60;		(*CH3 実行中I*)
D1303:=30;		(*CH3 実行中D*)
D1304:=0;		(*CH3 SV変化率下降*)
D1305:=0;		(*CH3 SV変化率上昇*)
D1306:=0;		(*CH3 プリセットマニュアル*)
D1308:=1;		(*CH3 実行中No*)
D1309:=234;		(*CH3 実行中SV*)
D1310:=30000;	(*CH3 実行中警報値1*)
D1311:=-30000;	(*CH3 実行中警報値2*)
D1401:=50;		(*CH4 実行中P*)
D1402:=60;		(*CH4 実行中I*)
D1403:=30;		(*CH4 実行中D*)
D1404:=0;		(*CH4 SV変化率下降*)
D1405:=0;		(*CH4 SV変化率上昇*)
D1406:=0;		(*CH4 プリセットマニュアル*)
D1408:=1;		(*CH4 実行中No*)
D1409:=234;		(*CH4 実行中SV*)
D1410:=30000;	(*CH4 実行中警報値1*)
D1411:=-30000;(*CH4 実行中警報値2*)
END_FUNCTION_BLOCK

PROGRAM 01_SB  // Initial
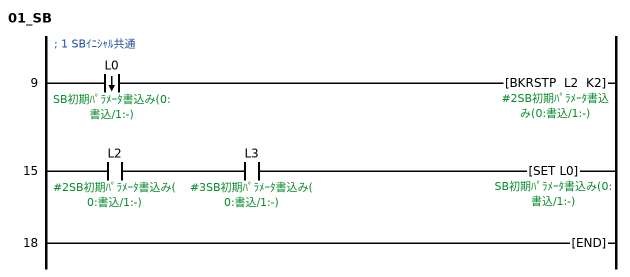
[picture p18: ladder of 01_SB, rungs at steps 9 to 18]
; 1 SBｲﾆｼｬﾙ共通
9     LDF     L0  ; SB初期ﾊﾟﾗﾒｰﾀ書込み(0:書込/1:-)
      BKRSTP  L2 K2  ; #2SB初期ﾊﾟﾗﾒｰﾀ書込み(0:書込/1:-)
15    LD      L2  ; #2SB初期ﾊﾟﾗﾒｰﾀ書込み(0:書込/1:-)
      AND     L3  ; #3SB初期ﾊﾟﾗﾒｰﾀ書込み(0:書込/1:-)
      SET     L0  ; SB初期ﾊﾟﾗﾒｰﾀ書込み(0:書込/1:-)
18    END
END_PROGRAM

PROGRAM 23_#3  // SB100
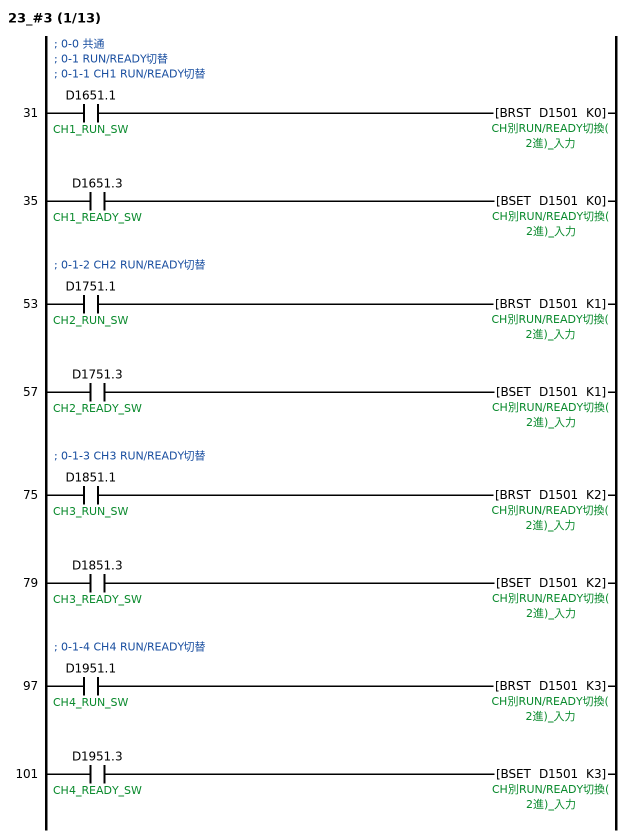
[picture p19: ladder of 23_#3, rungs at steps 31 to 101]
; 0-0 共通
; 0-1 RUN/READY切替
; 0-1-1 CH1 RUN/READY切替
31    LD      D1651.1  ; CH1_RUN_SW
      BRST    D1501 K0  ; CH別RUN/READY切換(2進)_入力
35    LD      D1651.3  ; CH1_READY_SW
      BSET    D1501 K0
; 0-1-2 CH2 RUN/READY切替
53    LD      D1751.1  ; CH2_RUN_SW
      BRST    D1501 K1
57    LD      D1751.3  ; CH2_READY_SW
      BSET    D1501 K1
; 0-1-3 CH3 RUN/READY切替
75    LD      D1851.1  ; CH3_RUN_SW
      BRST    D1501 K2
79    LD      D1851.3  ; CH3_READY_SW
      BSET    D1501 K2
; 0-1-4 CH4 RUN/READY切替
97    LD      D1951.1  ; CH4_RUN_SW
      BRST    D1501 K3
101   LD      D1951.3  ; CH4_READY_SW
      BSET    D1501 K3
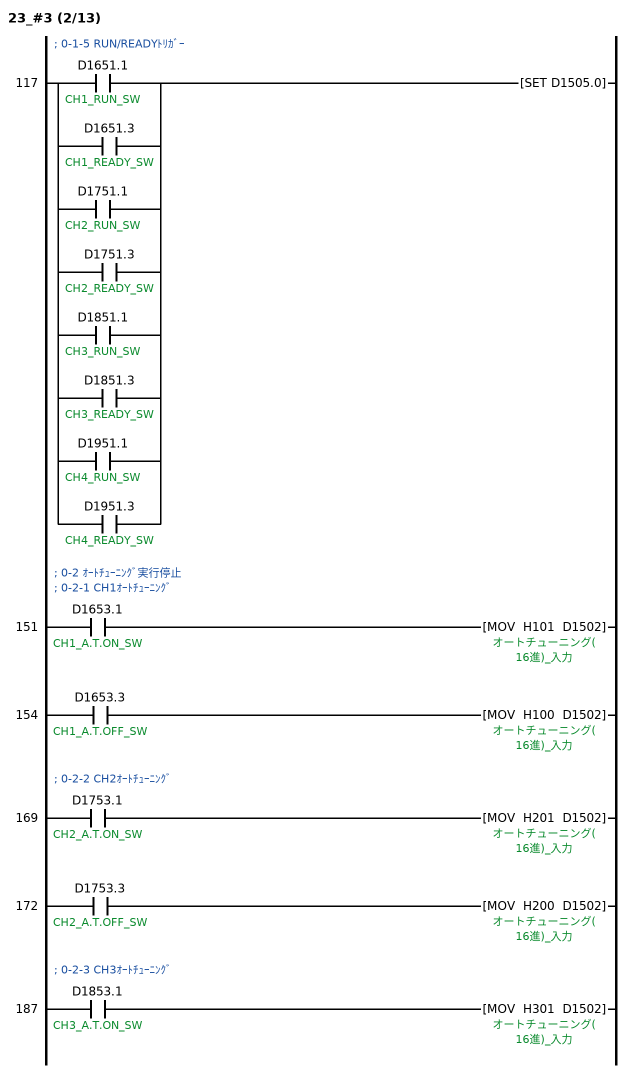
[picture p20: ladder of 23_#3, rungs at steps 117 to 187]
; 0-1-5 RUN/READYﾄﾘｶﾞｰ
117   LD      D1651.1  ; CH1_RUN_SW
      OR      D1651.3  ; CH1_READY_SW
      OR      D1751.1  ; CH2_RUN_SW
      OR      D1751.3  ; CH2_READY_SW
      OR      D1851.1  ; CH3_RUN_SW
      OR      D1851.3  ; CH3_READY_SW
      OR      D1951.1  ; CH4_RUN_SW
      OR      D1951.3  ; CH4_READY_SW
      SET     D1505.0
; 0-2 ｵｰﾄﾁｭｰﾆﾝｸﾞ実行停止
; 0-2-1 CH1ｵｰﾄﾁｭｰﾆﾝｸﾞ
151   LD      D1653.1  ; CH1_A.T.ON_SW
      MOV     H101 D1502  ; オートチューニング(16進)_入力
154   LD      D1653.3  ; CH1_A.T.OFF_SW
      MOV     H100 D1502
; 0-2-2 CH2ｵｰﾄﾁｭｰﾆﾝｸﾞ
169   LD      D1753.1  ; CH2_A.T.ON_SW
      MOV     H201 D1502
172   LD      D1753.3  ; CH2_A.T.OFF_SW
      MOV     H200 D1502
; 0-2-3 CH3ｵｰﾄﾁｭｰﾆﾝｸﾞ
187   LD      D1853.1  ; CH3_A.T.ON_SW
      MOV     H301 D1502
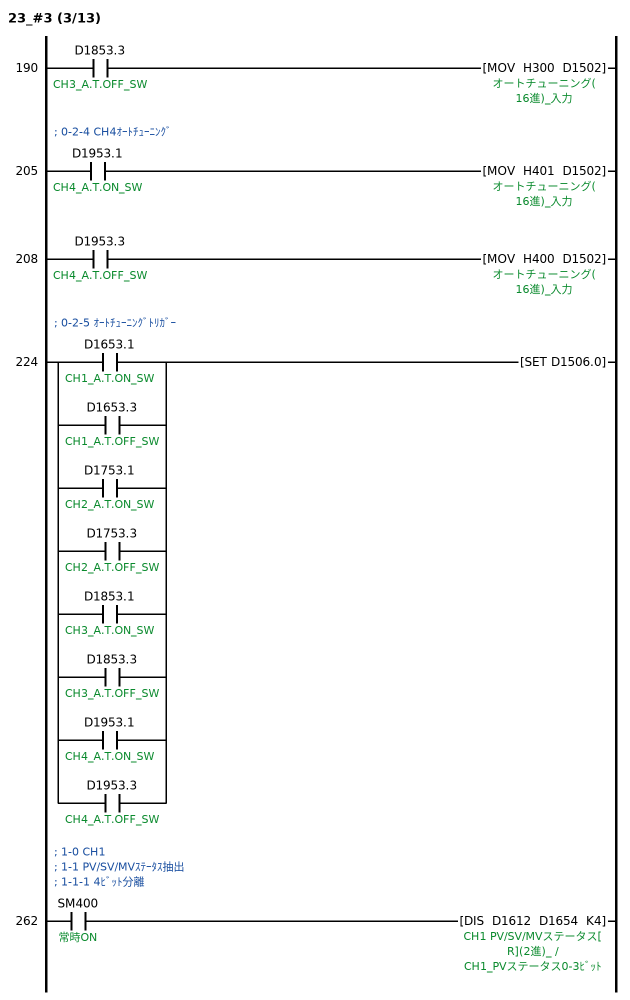
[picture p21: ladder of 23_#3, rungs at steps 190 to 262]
190   LD      D1853.3  ; CH3_A.T.OFF_SW
      MOV     H300 D1502
; 0-2-4 CH4ｵｰﾄﾁｭｰﾆﾝｸﾞ
205   LD      D1953.1  ; CH4_A.T.ON_SW
      MOV     H401 D1502
208   LD      D1953.3  ; CH4_A.T.OFF_SW
      MOV     H400 D1502
; 0-2-5 ｵｰﾄﾁｭｰﾆﾝｸﾞﾄﾘｶﾞｰ
224   LD      D1653.1  ; CH1_A.T.ON_SW
      OR      D1653.3  ; CH1_A.T.OFF_SW
      OR      D1753.1  ; CH2_A.T.ON_SW
      OR      D1753.3  ; CH2_A.T.OFF_SW
      OR      D1853.1  ; CH3_A.T.ON_SW
      OR      D1853.3  ; CH3_A.T.OFF_SW
      OR      D1953.1  ; CH4_A.T.ON_SW
      OR      D1953.3  ; CH4_A.T.OFF_SW
      SET     D1506.0
; 1-0 CH1
; 1-1 PV/SV/MVｽﾃｰﾀｽ抽出
; 1-1-1 4ﾋﾞｯﾄ分離
262   LD      SM400  ; 常時ON
      DIS     D1612 D1654 K4  ; CH1 PV/SV/MVステータス[R](2進)_ / CH1_PVステータス0-3ﾋﾞｯﾄ
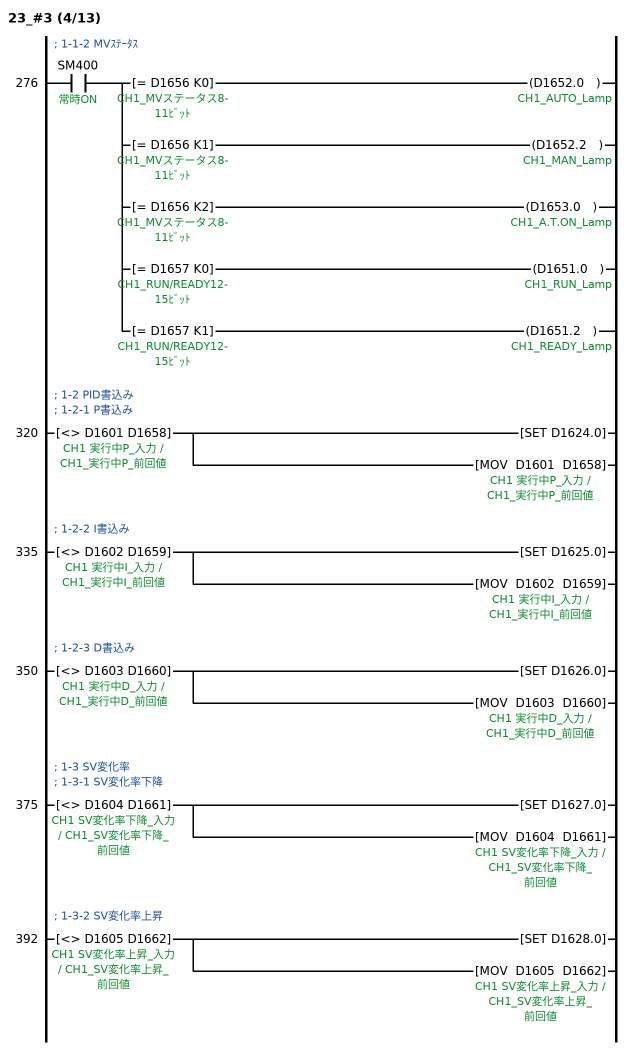
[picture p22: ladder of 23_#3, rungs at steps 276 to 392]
; 1-1-2 MVｽﾃｰﾀｽ
276   LD      SM400  ; 常時ON
      MPS
      AND=    D1656 K0  ; CH1_MVステータス8-11ﾋﾞｯﾄ
      OUT     D1652.0  ; CH1_AUTO_Lamp
      MRD
      AND=    D1656 K1  ; CH1_MVステータス8-11ﾋﾞｯﾄ
      OUT     D1652.2  ; CH1_MAN_Lamp
      MRD
      AND=    D1656 K2  ; CH1_MVステータス8-11ﾋﾞｯﾄ
      OUT     D1653.0  ; CH1_A.T.ON_Lamp
      MRD
      AND=    D1657 K0  ; CH1_RUN/READY12-15ﾋﾞｯﾄ
      OUT     D1651.0  ; CH1_RUN_Lamp
      MPP
      AND=    D1657 K1  ; CH1_RUN/READY12-15ﾋﾞｯﾄ
      OUT     D1651.2  ; CH1_READY_Lamp
; 1-2 PID書込み
; 1-2-1 P書込み
320   LD<>    D1601 D1658  ; CH1 実行中P_入力 / CH1_実行中P_前回値
      SET     D1624.0
      MOV     D1601 D1658
; 1-2-2 I書込み
335   LD<>    D1602 D1659  ; CH1 実行中I_入力 / CH1_実行中I_前回値
      SET     D1625.0
      MOV     D1602 D1659
; 1-2-3 D書込み
350   LD<>    D1603 D1660  ; CH1 実行中D_入力 / CH1_実行中D_前回値
      SET     D1626.0
      MOV     D1603 D1660
; 1-3 SV変化率
; 1-3-1 SV変化率下降
375   LD<>    D1604 D1661  ; CH1 SV変化率下降_入力 / CH1_SV変化率下降_前回値
      SET     D1627.0
      MOV     D1604 D1661
; 1-3-2 SV変化率上昇
392   LD<>    D1605 D1662  ; CH1 SV変化率上昇_入力 / CH1_SV変化率上昇_前回値
      SET     D1628.0
      MOV     D1605 D1662
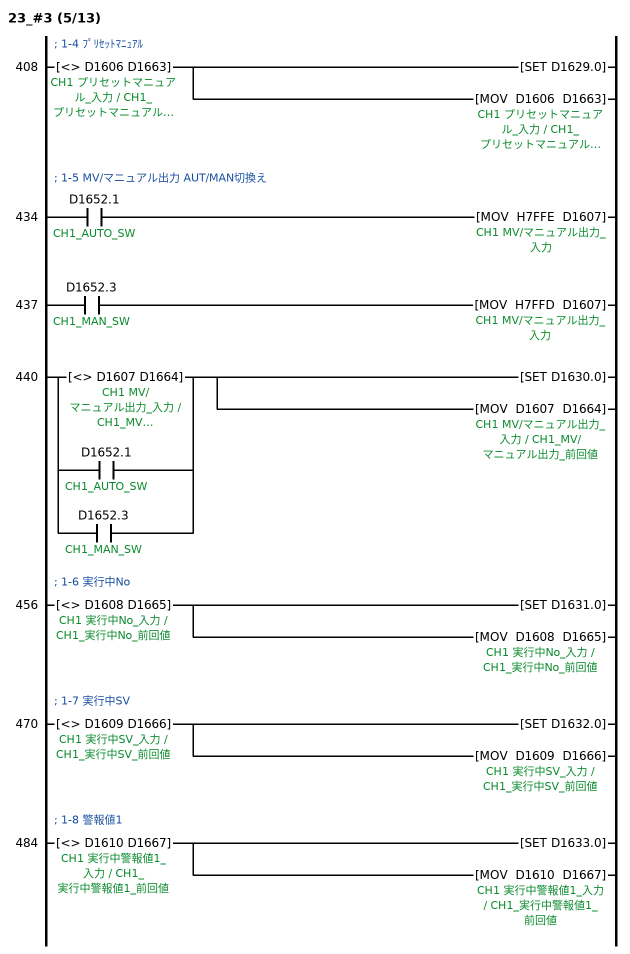
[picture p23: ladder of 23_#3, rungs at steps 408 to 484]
; 1-4 ﾌﾟﾘｾｯﾄﾏﾆｭｱﾙ
408   LD<>    D1606 D1663  ; CH1 プリセットマニュアル_入力 / CH1_プリセットマニュアル_前回値
      SET     D1629.0
      MOV     D1606 D1663
; 1-5 MV/マニュアル出力 AUT/MAN切換え
434   LD      D1652.1  ; CH1_AUTO_SW
      MOV     H7FFE D1607  ; CH1 MV/マニュアル出力_入力
437   LD      D1652.3  ; CH1_MAN_SW
      MOV     H7FFD D1607
440   LD<>    D1607 D1664  ; CH1 MV/マニュアル出力_入力 / CH1_MV/マニュアル出力_前回値
      OR      D1652.1  ; CH1_AUTO_SW
      OR      D1652.3  ; CH1_MAN_SW
      SET     D1630.0
      MOV     D1607 D1664
; 1-6 実行中No
456   LD<>    D1608 D1665  ; CH1 実行中No_入力 / CH1_実行中No_前回値
      SET     D1631.0
      MOV     D1608 D1665
; 1-7 実行中SV
470   LD<>    D1609 D1666  ; CH1 実行中SV_入力 / CH1_実行中SV_前回値
      SET     D1632.0
      MOV     D1609 D1666
; 1-8 警報値1
484   LD<>    D1610 D1667  ; CH1 実行中警報値1_入力 / CH1_実行中警報値1_前回値
      SET     D1633.0
      MOV     D1610 D1667
; 1-9 警報値2
498   LD<>    D1611 D1668  ; CH1 実行中警報値2_入力 / CH1_実行中警報値2_前回値
      SET     D1634.0
      MOV     D1611 D1668
; 2-0 CH2
; 2-1 PV/SV/MVｽﾃｰﾀｽ抽出
; 2-1-1 4ﾋﾞｯﾄ分離
533   LD      SM400  ; 常時ON
      DIS     D1712 D1754 K4  ; CH2 PV/SV/MVステータス[R](2進)_ / CH2_MVステータス0-3ﾋﾞｯﾄ
; 2-1-2 MVｽﾃｰﾀｽ
547   LD      SM400  ; 常時ON
      MPS
      AND=    D1756 K0  ; CH2_MVステータス8-11ﾋﾞｯﾄ
      OUT     D1752.0  ; CH2_AUTO_Lamp
      MRD
      AND=    D1756 K1  ; CH2_MVステータス8-11ﾋﾞｯﾄ
      OUT     D1752.2  ; CH2_MAN_Lamp
      MRD
      AND=    D1756 K2  ; CH2_MVステータス8-11ﾋﾞｯﾄ
      OUT     D1753.0  ; CH2_A.T.ON_Lamp
      MRD
      AND=    D1757 K0  ; CH2_MVステータス12-15ﾋﾞｯﾄ
      OUT     D1751.0  ; CH2_RUN_Lamp
      MPP
      AND=    D1757 K1  ; CH2_MVステータス12-15ﾋﾞｯﾄ
      OUT     D1751.2  ; CH2_READY_Lamp
; 2-2 PID書込み
; 2-2-1 P書込み
591   LD<>    D1701 D1758  ; CH2 実行中P_入力 / CH2_実行中P_前回値
      SET     D1724.0
      MOV     D1701 D1758
; 2-2-2 I書込み
606   LD<>    D1702 D1759  ; CH2 実行中I_入力 / CH2_実行中I_前回値
      SET     D1725.0
      MOV     D1702 D1759
; 2-2-3 D書込み
621   LD<>    D1703 D1760  ; CH2 実行中D_入力 / CH2_実行中D_前回値
      SET     D1726.0
      MOV     D1703 D1760
; 2-3 SV変化率
; 2-3-1 SV変化率下降
646   LD<>    D1704 D1761  ; CH2 SV変化率下降_入力 / CH2_SV変化率下降_前回値
      SET     D1727.0
      MOV     D1704 D1761
; 2-3-2 SV変化率上昇
663   LD<>    D1705 D1762  ; CH2 SV変化率上昇_入力 / CH2_SV変化率上昇_前回値
      SET     D1728.0
      MOV     D1705 D1762
; 2-4 ﾌﾟﾘｾｯﾄﾏﾆｭｱﾙ
679   LD<>    D1706 D1763  ; CH2 プリセットマニュアル_入力 / CH2_プリセットマニュアル_前回値
      SET     D1729.0
      MOV     D1706 D1763
; 2-5 MV/マニュアル出力 AUT/MAN切換え
705   LD      D1752.1  ; CH2_AUTO_SW
      MOV     H7FFE D1707  ; CH2 MV/マニュアル出力_入力
708   LD      D1752.3  ; CH2_MAN_SW
      MOV     H7FFD D1707
711   LD<>    D1707 D1764  ; CH2 MV/マニュアル出力_入力 / CH2_MV/マニュアル出力_前回値
      OR      D1752.1  ; CH2_AUTO_SW
      OR      D1752.3  ; CH2_MAN_SW
      SET     D1730.0
      MOV     D1707 D1764
; 2-6 実行中No
727   LD<>    D1708 D1765  ; CH2 実行中No_入力 / CH2_実行中No_前回値
      SET     D1731.0
      MOV     D1708 D1765
; 2-7 実行中SV
741   LD<>    D1709 D1766  ; CH2 実行中SV_入力 / CH2_実行中SV_前回値
      SET     D1732.0
      MOV     D1709 D1766
; 2-8 警報値1
755   LD<>    D1710 D1767  ; CH2 実行中警報値1_入力 / CH2_実行中警報値1_前回値
      SET     D1733.0
      MOV     D1710 D1767
; 2-9 警報値2
769   LD<>    D1711 D1768  ; CH2 実行中警報値2_入力 / CH2_実行中警報値2_前回値
      SET     D1734.0
      MOV     D1711 D1768
; 3-0 CH3
; 3-1 PV/SV/MVｽﾃｰﾀｽ抽出
; 3-1-1 4ﾋﾞｯﾄ分離
804   LD      SM400  ; 常時ON
      DIS     D1812 D1854 K4  ; CH3 PV/SV/MVステータス[R](2進)_ / CH3_MVステータス0-3ﾋﾞｯﾄ
; 3-1-2 MVｽﾃｰﾀｽ
818   LD      SM400  ; 常時ON
      MPS
      AND=    D1856 K0  ; CH3_MVステータス8-11ﾋﾞｯﾄ
      OUT     D1852.0  ; CH3_AUTO_Lamp
      MRD
      AND=    D1856 K1  ; CH3_MVステータス8-11ﾋﾞｯﾄ
      OUT     D1852.2  ; CH3_MAN_Lamp
      MRD
      AND=    D1856 K2  ; CH3_MVステータス8-11ﾋﾞｯﾄ
      OUT     D1853.0  ; CH3_A.T.ON_Lamp
      MRD
      AND=    D1857 K0  ; CH3_MVステータス12-15ﾋﾞｯﾄ
      OUT     D1851.0  ; CH3_RUN_Lamp
      MPP
      AND=    D1857 K1  ; CH3_MVステータス12-15ﾋﾞｯﾄ
      OUT     D1851.2  ; CH3_READY_Lamp
; 3-2 PID書込み
; 3-2-1 P書込み
862   LD<>    D1801 D1858  ; CH3 実行中P_入力 / CH3_実行中P_前回値
      SET     D1824.0
      MOV     D1801 D1858
; 3-2-2 I書込み
877   LD<>    D1802 D1859  ; CH3 実行中I_入力 / CH3_実行中I_前回値
      SET     D1825.0
      MOV     D1802 D1859
; 3-2-3 D書込み
892   LD<>    D1803 D1860  ; CH3 実行中D_入力 / CH3_実行中D_前回値
      SET     D1826.0
      MOV     D1803 D1860
; 3-3 SV変化率
; 3-3-1 SV変化率下降
917   LD<>    D1804 D1861  ; CH3 SV変化率下降_入力 / CH3_SV変化率下降_前回値
      SET     D1827.0
      MOV     D1804 D1861
; 3-3-2 SV変化率上昇
934   LD<>    D1805 D1862  ; CH3 SV変化率上昇_入力 / CH3_SV変化率上昇_前回値
      SET     D1828.0
      MOV     D1805 D1862
; 3-4 ﾌﾟﾘｾｯﾄﾏﾆｭｱﾙ
950   LD<>    D1806 D1863  ; CH3 プリセットマニュアル_入力 / CH3_プリセットマニュアル_前回値
      SET     D1829.0
      MOV     D1806 D1863
; 3-5 MV/マニュアル出力 AUT/MAN切換え
976   LD      D1852.1  ; CH3_AUTO_SW
      MOV     H7FFE D1807  ; CH3 MV/マニュアル出力_入力
979   LD      D1852.3  ; CH3_MAN_SW
      MOV     H7FFD D1807
982   LD<>    D1807 D1864  ; CH3 MV/マニュアル出力_入力 / CH3_MV/マニュアル出力_前回値
      OR      D1852.1  ; CH3_AUTO_SW
      OR      D1852.3  ; CH3_MAN_SW
      SET     D1830.0
      MOV     D1807 D1864
; 3-6 実行中No
998   LD<>    D1808 D1865  ; CH3 実行中No_入力 / CH3_実行中No_前回値
      SET     D1831.0
      MOV     D1808 D1865
; 3-7 実行中SV
1012  LD<>    D1809 D1866  ; CH3 実行中SV_入力 / CH3_実行中SV_前回値
      SET     D1832.0
      MOV     D1809 D1866
; 3-8 警報値1
1026  LD<>    D1810 D1867  ; CH3 実行中警報値1_入力 / CH3_実行中警報値1_前回値
      SET     D1833.0
      MOV     D1810 D1867
; 3-9 警報値2
1040  LD<>    D1811 D1868  ; CH3 実行中警報値2_入力 / CH3_実行中警報値2_前回値
      SET     D1834.0
      MOV     D1811 D1868
; 4-0 CH4
; 4-1 PV/SV/MVｽﾃｰﾀｽ抽出
; 4-1-1 4ﾋﾞｯﾄ分離
1075  LD      SM400  ; 常時ON
      DIS     D1912 D1954 K4  ; CH4 PV/SV/MVステータス[R](2進)_ / CH4_MVステータス0-3ﾋﾞｯﾄ
; 4-1-2 MVｽﾃｰﾀｽ
1089  LD      SM400  ; 常時ON
      MPS
      AND=    D1956 K0  ; CH4_MVステータス8-11ﾋﾞｯﾄ
      OUT     D1952.0  ; CH4_AUTO_Lamp
      MRD
      AND=    D1956 K1  ; CH4_MVステータス8-11ﾋﾞｯﾄ
      OUT     D1952.2  ; CH4_MAN_Lamp
      MRD
      AND=    D1956 K2  ; CH4_MVステータス8-11ﾋﾞｯﾄ
      OUT     D1953.0  ; CH4_A.T.ON_Lamp
      MRD
      AND=    D1957 K0  ; CH4_MVステータス12-15ﾋﾞｯﾄ
      OUT     D1951.0  ; CH4_RUN_Lamp
      MPP
      AND=    D1957 K1  ; CH4_MVステータス12-15ﾋﾞｯﾄ
      OUT     D1951.2  ; CH4_READY_Lamp
; 4-2 PID書込み
; 4-2-1 P書込み
1133  LD<>    D1901 D1958  ; CH4 実行中P_入力 / CH4_実行中P_前回値
      SET     D1924.0
      MOV     D1901 D1958
; 4-2-2 I書込み
1148  LD<>    D1902 D1959  ; CH4 実行中I_入力 / CH4_実行中I_前回値
      SET     D1925.0
      MOV     D1902 D1959
; 4-2-3 D書込み
1163  LD<>    D1903 D1960  ; CH4 実行中D_入力 / CH4_実行中D_前回値
      SET     D1926.0
      MOV     D1903 D1960
; 4-3 SV変化率
; 4-3-1 SV変化率下降
1188  LD<>    D1904 D1961  ; CH4 SV変化率下降_入力 / CH4_SV変化率下降_前回値
      SET     D1927.0
      MOV     D1904 D1961
; 4-3-2 SV変化率上昇
1205  LD<>    D1905 D1962  ; CH4 SV変化率上昇_入力 / CH4_SV変化率上昇_前回値
      SET     D1928.0
      MOV     D1905 D1962
; 4-4 ﾌﾟﾘｾｯﾄﾏﾆｭｱﾙ
1221  LD<>    D1906 D1963  ; CH4 プリセットマニュアル_入力 / CH4_プリセットマニュアル_前回値
      SET     D1929.0
      MOV     D1906 D1963
; 4-5 MV/マニュアル出力 AUT/MAN切換え
1247  LD      D1952.1  ; CH4_AUTO_SW
      MOV     H7FFE D1907  ; CH4 MV/マニュアル出力_入力
1250  LD      D1952.3  ; CH4_MAN_SW
      MOV     H7FFD D1907
1253  LD<>    D1907 D1964  ; CH4 MV/マニュアル出力_入力 / CH4_MV/マニュアル出力_前回値
      OR      D1952.1  ; CH4_AUTO_SW
      OR      D1952.3  ; CH4_MAN_SW
      SET     D1930.0
      MOV     D1907 D1964
; 4-6 実行中No
1269  LD<>    D1908 D1965  ; CH4 実行中No_入力 / CH4_実行中No_前回値
      SET     D1931.0
      MOV     D1908 D1965
; 4-7 実行中SV
1283  LD<>    D1909 D1966  ; CH4 実行中SV_入力 / CH4_実行中SV_前回値
      SET     D1932.0
      MOV     D1909 D1966
; 4-8 警報値1
1297  LD<>    D1910 D1967  ; CH4 実行中警報値1_入力 / CH4_実行中警報値1_前回値
      SET     D1933.0
      MOV     D1910 D1967
; 4-9 警報値2
1311  LD<>    D1911 D1968  ; CH4 実行中警報値2_入力 / CH4_実行中警報値2_前回値
      SET     D1934.0
      MOV     D1911 D1968
1317  END
END_PROGRAM

PROGRAM 03_#3  // SB_Initial
VAR
  __IST_5cbe4b41e3514949 : I+ST_5cbe4b41e3514949;
END_VAR
; FB BLK START I+ST_5cbe4b41e3514949(__IST_5cbe4b41e3514949)
; 1 SB初期化ﾊﾟﾗﾒｰﾀ設定
13    LDI     L3  ; #3SB初期ﾊﾟﾗﾒｰﾀ書込み(0:書込/1:-)
      OUT     ___IST_EN_IN
; FB START
; FB_NAME I+ST_5cbe4b41e3514949
; INSTANCE_NAME __IST_5cbe4b41e3514949
; FB IN_B:__IST_EN_IN
; FB OUT___IST_EN_OUT:B
; FB END
; FB BLK END
; 2 実行中No書込み
33    LDI     L3  ; #3SB初期ﾊﾟﾗﾒｰﾀ書込み(0:書込/1:-)
      SET     D1631.0
      SET     D1731.0
      SET     D1831.0
      SET     D1931.0
; 3 実行中No書込み後待機
51    LDI     L3  ; #3SB初期ﾊﾟﾗﾒｰﾀ書込み(0:書込/1:-)
      OR      M11  ; SB_初期化ｷｰ保持(PID書込用)
      ANI     T3  ; #3SB PID書込みT
      OUT     M11  ; SB_初期化ｷｰ保持(PID書込用)
      OUT     T3 K10  ; #3SB PID書込みT
; 4 実行中No以外書込み
71    LDP     T3  ; #3SB PID書込みT
      FMOV    K1 D1624 K7  ; CH1 実行中P_ﾄﾘｶﾞｰ
      FMOV    K1 D1632 K3  ; CH1 実行中SV_ﾄﾘｶﾞｰ
81    LDP     T3  ; #3SB PID書込みT
      FMOV    K1 D1724 K7  ; CH2 実行中P_ﾄﾘｶﾞｰ
      FMOV    K1 D1732 K3  ; CH2 実行中SV_ﾄﾘｶﾞｰ
91    LDP     T3  ; #3SB PID書込みT
      FMOV    K1 D1824 K7  ; CH3 実行中P_ﾄﾘｶﾞｰ
      FMOV    K1 D1832 K3  ; CH3 実行中SV_ﾄﾘｶﾞｰ
101   LDP     T3  ; #3SB PID書込みT
      FMOV    K1 D1924 K7  ; CH4 実行中P_ﾄﾘｶﾞｰ
      FMOV    K1 D1932 K3  ; CH4 実行中SV_ﾄﾘｶﾞｰ
; 5 初期化ﾌﾗｸﾞｾｯﾄ
121   LD      SM400  ; 常時ON
      SET     L3  ; #3SB初期ﾊﾟﾗﾒｰﾀ書込み(0:書込/1:-)
123   END
END_PROGRAM

FUNCTION_BLOCK I+ST_5cbe4b41e3514949
VAR_INPUT
  __IST_EN_IN : BOOL;
END_VAR
VAR_OUTPUT
  __IST_EN_OUT : BOOL;
END_VAR
(* IST HEADER START *)
IF NOT __IST_EN_IN THEN __IST_EN_OUT:=FALSE; RETURN; END_IF;
(* VERSION=1:TYPE=STB *)
(* IST HEADER END *)
D1601:=50;		(*CH1 実行中P*)
D1602:=60;		(*CH1 実行中I*)
D1603:=30;		(*CH1 実行中D*)
D1604:=0;		(*CH1 SV変化率下降*)
D1605:=0;		(*CH1 SV変化率上昇*)
D1606:=0;		(*CH1 プリセットマニュアル*)
D1608:=1;		(*CH1 実行中No*)
D1609:=234;		(*CH1 実行中SV*)
D1610:=30000;	(*CH1 実行中警報値1*)
D1611:=-30000;	(*CH1 実行中警報値2*)
D1701:=50;		(*CH2 実行中P*)
D1702:=60;		(*CH2 実行中I*)
D1703:=30;		(*CH2 実行中D*)
D1704:=0;		(*CH2 SV変化率下降*)
D1705:=0;		(*CH2 SV変化率上昇*)
D1706:=0;		(*CH2 プリセットマニュアル*)
D1708:=1;		(*CH2 実行中No*)
D1709:=234;		(*CH2 実行中SV*)
D1710:=30000;	(*CH2 実行中警報値1*)
D1711:=-30000;	(*CH2 実行中警報値2*)
D1801:=50;		(*CH3 実行中P*)
D1802:=60;		(*CH3 実行中I*)
D1803:=30;		(*CH3 実行中D*)
D1804:=0;		(*CH3 SV変化率下降*)
D1805:=0;		(*CH3 SV変化率上昇*)
D1806:=0;		(*CH3 プリセットマニュアル*)
D1808:=1;		(*CH3 実行中No*)
D1809:=234;		(*CH3 実行中SV*)
D1810:=30000;	(*CH3 実行中警報値1*)
D1811:=-30000;	(*CH3 実行中警報値2*)
D1901:=50;		(*CH4 実行中P*)
D1902:=60;		(*CH4 実行中I*)
D1903:=30;		(*CH4 実行中D*)
D1904:=0;		(*CH4 SV変化率下降*)
D1905:=0;		(*CH4 SV変化率上昇*)
D1906:=0;		(*CH4 プリセットマニュアル*)
D1908:=1;		(*CH4 実行中No*)
D1909:=234;		(*CH4 実行中SV*)
D1910:=30000;	(*CH4 実行中警報値1*)
D1911:=-30000;(*CH4 実行中警報値2*)
END_FUNCTION_BLOCK

// device comments not shown above
D71  ; GOTﾍﾞｰｽ画面
D72  ; GOTｵｰﾊﾞｰﾗｯﾌﾟｳｨﾝﾄﾞｳ
D73  ; GOTｽｰﾊﾟｰｲﾝﾎﾟｰｽﾞｳｨﾝﾄﾞｳ
D80  ; GOTｼｽﾃﾑ信号1-1
D81  ; GOTｼｽﾃﾑ信号2-1
D82  ; GOT数値入力番号
D83  ; GOT数値入力変更前値(32ﾋﾞｯﾄ)
D84  ; GOT数値入力変更前値(32ﾋﾞｯﾄ)
D85  ; GOT数値入力変更後値(32ﾋﾞｯﾄ)
D86  ; GOT数値入力変更後値(32ﾋﾞｯﾄ)
D87  ; GOTｴﾗｰｺｰﾄﾞ
D88  ; GOTｴﾗｰｺｰﾄﾞ2
D89  ; GOT印字中ﾚﾎﾟｰﾄ画面番号
D90  ; GOT表示中ﾍﾞｰｽ画面番号
D91  ; GOT表示中ｳｨﾝﾄﾞｳ1画面番号
D92  ; GOT現在ｶｰｿﾙ表示ｵﾌﾞｼﾞｪｸﾄID
D93  ; GOT前回ｶｰｿﾙ表示ｵﾌﾞｼﾞｪｸﾄID
D94  ; GOT現在ｶｰｿﾙ表示ﾕｰｻﾞID
D95  ; GOT前回ｶｰｿﾙ表示ﾕｰｻﾞID
D96  ; GOT入力ｷｰｺｰﾄﾞ
D97  ; GOT外部入出力機能･入力情報1
D98  ; GOT外部入出力機能･入力情報2
D103  ; SBｼｽﾃﾑｴﾗｰ失敗ﾃﾞﾊﾞｲｽ
D104  ; SBｼｽﾃﾑｴﾗｰｴﾗｰﾃﾞﾊﾞｲｽ
D1003  ; CH別RUN/READY切換(2進)_表示
D1004  ; オートチューニング(16進)_表示
D1005  ; CH別RUN/READY切換(2進)_ﾄﾘｶﾞｰ
D1006  ; オートチューニング(16進)_ﾄﾘｶﾞｰ
D1011  ; CH1PV_表示
D1012  ; CH2PV_表示
D1013  ; CH3PV_表示
D1014  ; CH4PV_表示
D1015  ; CH1SV_表示
D1016  ; CH2SV_表示
D1017  ; CH3SV_表示
D1018  ; CH4SV_表示
D1019  ; CH1MV_表示
D1020  ; CH2MV_表示
D1021  ; CH3MV_表示
D1022  ; CH4MV_表示
D1023  ; ALステータス1_表示
D1024  ; ALステータス2_表示
D1113  ; CH1 実行中P_表示
D1114  ; CH1 実行中I_表示
D1115  ; CH1 実行中D_表示
D1116  ; CH1 SV変化率下降_表示
D1117  ; CH1 SV変化率上昇_表示
D1118  ; CH1 プリセットマニュアル_表示
D1119  ; CH1 MV/マニュアル出力_表示
D1120  ; CH1 実行中No_表示
D1121  ; CH1 実行中SV_表示
D1122  ; CH1 実行中警報値1_表示
D1123  ; CH1 実行中警報値2_表示
D1125  ; CH1 実行中I_ﾄﾘｶﾞｰ
D1126  ; CH1 実行中D_ﾄﾘｶﾞｰ
D1127  ; CH1 SV変化率下降_ﾄﾘｶﾞｰ
D1128  ; CH1 SV変化率上昇_ﾄﾘｶﾞｰ
D1129  ; CH1 プリセットマニュアル_ﾄﾘｶﾞｰ
D1130  ; CH1 MV/マニュアル出力_ﾄﾘｶﾞｰ
D1131  ; CH1 実行中No_ﾄﾘｶﾞｰ
D1133  ; CH1 実行中警報値1_ﾄﾘｶﾞｰ
D1134  ; CH1 実行中警報値2_ﾄﾘｶﾞｰ
D1151  ; CH1_RUNREADY
D1152  ; CH1_AUTOMAN
D1153  ; CH1_A.T
D1155  ; CH1_SVステータス4-7ﾋﾞｯﾄ
D1213  ; CH2 実行中P_表示
D1214  ; CH2 実行中I_表示
D1215  ; CH2 実行中D_表示
D1216  ; CH2 SV変化率下降_表示
D1217  ; CH2 SV変化率上昇_表示
D1218  ; CH2 プリセットマニュアル_表示
D1219  ; CH2 MV/マニュアル出力_表示
D1220  ; CH2 実行中No_表示
D1221  ; CH2 実行中SV_表示
D1222  ; CH2 実行中警報値1_表示
D1223  ; CH2 実行中警報値2_表示
D1225  ; CH2 実行中I_ﾄﾘｶﾞｰ
D1226  ; CH2 実行中D_ﾄﾘｶﾞｰ
D1227  ; CH2 SV変化率下降_ﾄﾘｶﾞｰ
D1228  ; CH2 SV変化率上昇_ﾄﾘｶﾞｰ
D1229  ; CH2 プリセットマニュアル_ﾄﾘｶﾞｰ
D1230  ; CH2 MV/マニュアル出力_ﾄﾘｶﾞｰ
D1231  ; CH2 実行中No_ﾄﾘｶﾞｰ
D1233  ; CH2 実行中警報値1_ﾄﾘｶﾞｰ
D1234  ; CH2 実行中警報値2_ﾄﾘｶﾞｰ
D1251  ; CH2_RUNREADY
D1252  ; CH2_AUTOMAN
D1253  ; CH2_A.T
D1255  ; CH2_MVステータス4-7ﾋﾞｯﾄ
D1313  ; CH3 実行中P_表示
D1314  ; CH3 実行中I_表示
D1315  ; CH3 実行中D_表示
D1316  ; CH3 SV変化率下降_表示
D1317  ; CH3 SV変化率上昇_表示
D1318  ; CH3 プリセットマニュアル_表示
D1319  ; CH3 MV/マニュアル出力_表示
D1320  ; CH3 実行中No_表示
D1321  ; CH3 実行中SV_表示
D1322  ; CH3 実行中警報値1_表示
D1323  ; CH3 実行中警報値2_表示
D1325  ; CH3 実行中I_ﾄﾘｶﾞｰ
D1326  ; CH3 実行中D_ﾄﾘｶﾞｰ
D1327  ; CH3 SV変化率下降_ﾄﾘｶﾞｰ
D1328  ; CH3 SV変化率上昇_ﾄﾘｶﾞｰ
D1329  ; CH3 プリセットマニュアル_ﾄﾘｶﾞｰ
D1330  ; CH3 MV/マニュアル出力_ﾄﾘｶﾞｰ
D1331  ; CH3 実行中No_ﾄﾘｶﾞｰ
D1333  ; CH3 実行中警報値1_ﾄﾘｶﾞｰ
D1334  ; CH3 実行中警報値2_ﾄﾘｶﾞｰ
D1351  ; CH3_RUNREADY
D1352  ; CH3_AUTOMAN
D1353  ; CH3_A.T
D1355  ; CH3_MVステータス4-7ﾋﾞｯﾄ
D1413  ; CH4 実行中P_表示
D1414  ; CH4 実行中I_表示
D1415  ; CH4 実行中D_表示
D1416  ; CH4 SV変化率下降_表示
D1417  ; CH4 SV変化率上昇_表示
D1418  ; CH4 プリセットマニュアル_表示
D1419  ; CH4 MV/マニュアル出力_表示
D1420  ; CH4 実行中No_表示
D1421  ; CH4 実行中SV_表示
D1422  ; CH4 実行中警報値1_表示
D1423  ; CH4 実行中警報値2_表示
D1425  ; CH4 実行中I_ﾄﾘｶﾞｰ
D1426  ; CH4 実行中D_ﾄﾘｶﾞｰ
D1427  ; CH4 SV変化率下降_ﾄﾘｶﾞｰ
D1428  ; CH4 SV変化率上昇_ﾄﾘｶﾞｰ
D1429  ; CH4 プリセットマニュアル_ﾄﾘｶﾞｰ
D1430  ; CH4 MV/マニュアル出力_ﾄﾘｶﾞｰ
D1431  ; CH4 実行中No_ﾄﾘｶﾞｰ
D1433  ; CH4 実行中警報値1_ﾄﾘｶﾞｰ
D1434  ; CH4 実行中警報値2_ﾄﾘｶﾞｰ
D1451  ; CH4_RUNREADY
D1452  ; CH4_AUTOMAN
D1453  ; CH4_A.T
D1455  ; CH4_MVステータス4-7ﾋﾞｯﾄ
D1503  ; CH別RUN/READY切換(2進)_表示
D1504  ; オートチューニング(16進)_表示
D1505  ; CH別RUN/READY切換(2進)_ﾄﾘｶﾞｰ
D1506  ; オートチューニング(16進)_ﾄﾘｶﾞｰ
D1511  ; CH1PV_表示
D1512  ; CH2PV_表示
D1513  ; CH3PV_表示
D1514  ; CH4PV_表示
D1515  ; CH1SV_表示
D1516  ; CH2SV_表示
D1517  ; CH3SV_表示
D1518  ; CH4SV_表示
D1519  ; CH1MV_表示
D1520  ; CH2MV_表示
D1521  ; CH3MV_表示
D1522  ; CH4MV_表示
D1523  ; ALステータス1_表示
D1524  ; ALステータス2_表示
D1613  ; CH1 実行中P_表示
D1614  ; CH1 実行中I_表示
D1615  ; CH1 実行中D_表示
D1616  ; CH1 SV変化率下降_表示
D1617  ; CH1 SV変化率上昇_表示
D1618  ; CH1 プリセットマニュアル_表示
D1619  ; CH1 MV/マニュアル出力_表示
D1620  ; CH1 実行中No_表示
D1621  ; CH1 実行中SV_表示
D1622  ; CH1 実行中警報値1_表示
D1623  ; CH1 実行中警報値2_表示
D1625  ; CH1 実行中I_ﾄﾘｶﾞｰ
D1626  ; CH1 実行中D_ﾄﾘｶﾞｰ
D1627  ; CH1 SV変化率下降_ﾄﾘｶﾞｰ
D1628  ; CH1 SV変化率上昇_ﾄﾘｶﾞｰ
D1629  ; CH1 プリセットマニュアル_ﾄﾘｶﾞｰ
D1630  ; CH1 MV/マニュアル出力_ﾄﾘｶﾞｰ
D1631  ; CH1 実行中No_ﾄﾘｶﾞｰ
D1633  ; CH1 実行中警報値1_ﾄﾘｶﾞｰ
D1634  ; CH1 実行中警報値2_ﾄﾘｶﾞｰ
D1651  ; CH1_RUNREADY
D1652  ; CH1_AUTOMAN
D1653  ; CH1_A.T
D1655  ; CH1_SVステータス4-7ﾋﾞｯﾄ
D1713  ; CH2 実行中P_表示
D1714  ; CH2 実行中I_表示
D1715  ; CH2 実行中D_表示
D1716  ; CH2 SV変化率下降_表示
D1717  ; CH2 SV変化率上昇_表示
D1718  ; CH2 プリセットマニュアル_表示
D1719  ; CH2 MV/マニュアル出力_表示
D1720  ; CH2 実行中No_表示
D1721  ; CH2 実行中SV_表示
D1722  ; CH2 実行中警報値1_表示
D1723  ; CH2 実行中警報値2_表示
D1725  ; CH2 実行中I_ﾄﾘｶﾞｰ
D1726  ; CH2 実行中D_ﾄﾘｶﾞｰ
D1727  ; CH2 SV変化率下降_ﾄﾘｶﾞｰ
D1728  ; CH2 SV変化率上昇_ﾄﾘｶﾞｰ
D1729  ; CH2 プリセットマニュアル_ﾄﾘｶﾞｰ
D1730  ; CH2 MV/マニュアル出力_ﾄﾘｶﾞｰ
D1731  ; CH2 実行中No_ﾄﾘｶﾞｰ
D1733  ; CH2 実行中警報値1_ﾄﾘｶﾞｰ
D1734  ; CH2 実行中警報値2_ﾄﾘｶﾞｰ
D1751  ; CH2_RUNREADY
D1752  ; CH2_AUTOMAN
D1753  ; CH2_A.T
D1755  ; CH2_MVステータス4-7ﾋﾞｯﾄ
D1813  ; CH3 実行中P_表示
D1814  ; CH3 実行中I_表示
D1815  ; CH3 実行中D_表示
D1816  ; CH3 SV変化率下降_表示
D1817  ; CH3 SV変化率上昇_表示
D1818  ; CH3 プリセットマニュアル_表示
D1819  ; CH3 MV/マニュアル出力_表示
D1820  ; CH3 実行中No_表示
D1821  ; CH3 実行中SV_表示
D1822  ; CH3 実行中警報値1_表示
D1823  ; CH3 実行中警報値2_表示
D1825  ; CH3 実行中I_ﾄﾘｶﾞｰ
D1826  ; CH3 実行中D_ﾄﾘｶﾞｰ
D1827  ; CH3 SV変化率下降_ﾄﾘｶﾞｰ
D1828  ; CH3 SV変化率上昇_ﾄﾘｶﾞｰ
D1829  ; CH3 プリセットマニュアル_ﾄﾘｶﾞｰ
D1830  ; CH3 MV/マニュアル出力_ﾄﾘｶﾞｰ
D1831  ; CH3 実行中No_ﾄﾘｶﾞｰ
D1833  ; CH3 実行中警報値1_ﾄﾘｶﾞｰ
D1834  ; CH3 実行中警報値2_ﾄﾘｶﾞｰ
D1851  ; CH3_RUNREADY
D1852  ; CH3_AUTOMAN
D1853  ; CH3_A.T
D1855  ; CH3_MVステータス4-7ﾋﾞｯﾄ
D1913  ; CH4 実行中P_表示
D1914  ; CH4 実行中I_表示
D1915  ; CH4 実行中D_表示
D1916  ; CH4 SV変化率下降_表示
D1917  ; CH4 SV変化率上昇_表示
D1918  ; CH4 プリセットマニュアル_表示
D1919  ; CH4 MV/マニュアル出力_表示
D1920  ; CH4 実行中No_表示
D1921  ; CH4 実行中SV_表示
D1922  ; CH4 実行中警報値1_表示
D1923  ; CH4 実行中警報値2_表示
D1925  ; CH4 実行中I_ﾄﾘｶﾞｰ
D1926  ; CH4 実行中D_ﾄﾘｶﾞｰ
D1927  ; CH4 SV変化率下降_ﾄﾘｶﾞｰ
D1928  ; CH4 SV変化率上昇_ﾄﾘｶﾞｰ
D1929  ; CH4 プリセットマニュアル_ﾄﾘｶﾞｰ
D1930  ; CH4 MV/マニュアル出力_ﾄﾘｶﾞｰ
D1931  ; CH4 実行中No_ﾄﾘｶﾞｰ
D1933  ; CH4 実行中警報値1_ﾄﾘｶﾞｰ
D1934  ; CH4 実行中警報値2_ﾄﾘｶﾞｰ
D1951  ; CH4_RUNREADY
D1952  ; CH4_AUTOMAN
D1953  ; CH4_A.T
D1955  ; CH4_MVステータス4-7ﾋﾞｯﾄ
D80.0  ; GOT自動ｽｸﾘｰﾝｾｰﾌﾞ無効信号
D80.1  ; GOT強制ｽｸﾘｰﾝｾｰﾌﾞ番号
D80.2  ; GOT強制ｽｸﾘｰﾝｾｰﾌﾞﾀｯﾁ解除信号
D80.3  ; GOT入力ｷｰ読出し完了信号
D80.4  ; GOT数値入力読出し完了信号
D80.5  ; GOTﾊﾞｰｺｰﾄﾞ入力無効信号(CH8)
D80.6  ; GOT外部機器入出力完了信号(CH8)
D80.7  ; GOT使用禁止
D80.8  ; GOTﾌﾞｻﾞｰｽﾘｰｼｮｯﾄ出力信号
D80.9  ; GOTﾀｯﾁ操作無効信号
D80.A  ; GOTﾊｰﾄﾞｺﾋﾟｰ設定有効信号
D80.B  ; GOT使用禁止
D80.C  ; GOTﾊｰﾄﾞｺﾋﾟｰ白黒反転信号
D80.D  ; GOTｴﾗｰﾘｾｯﾄ信号
D80.F  ; GOTﾌﾞｻﾞｰﾜﾝｼｮｯﾄ出力信号
D1023.0  ; CH1_AL1_表示
D1023.2  ; CH1_AL2_表示
D1023.4  ; CH1_AL3_表示
D1023.6  ; CH1_AL4_表示
D1023.8  ; CH2_AL1_表示
D1023.A  ; CH2_AL2_表示
D1023.C  ; CH2_AL3_表示
D1023.E  ; CH2_AL4_表示
D1024.0  ; CH3_AL1_表示
D1024.2  ; CH3_AL2_表示
D1024.4  ; CH3_AL3_表示
D1024.6  ; CH3_AL4_表示
D1024.8  ; CH4_AL1_表示
D1024.A  ; CH4_AL2_表示
D1024.C  ; CH4_AL3_表示
D1024.E  ; CH4_AL4_表示
D1153.2  ; CH1_A.T.OFF_Lamp
D1253.2  ; CH2_A.T.OFF_Lamp
D1353.2  ; CH3_A.T.OFF_Lamp
D1453.2  ; CH4_A.T.OFF_Lamp
D1523.0  ; CH1_AL1_表示
D1523.2  ; CH1_AL2_表示
D1523.4  ; CH1_AL3_表示
D1523.6  ; CH1_AL4_表示
D1523.8  ; CH2_AL1_表示
D1523.A  ; CH2_AL2_表示
D1523.C  ; CH2_AL3_表示
D1523.E  ; CH2_AL4_表示
D1524.0  ; CH3_AL1_表示
D1524.2  ; CH3_AL2_表示
D1524.4  ; CH3_AL3_表示
D1524.6  ; CH3_AL4_表示
D1524.8  ; CH4_AL1_表示
D1524.A  ; CH4_AL2_表示
D1524.C  ; CH4_AL3_表示
D1524.E  ; CH4_AL4_表示
D1653.2  ; CH1_A.T.OFF_Lamp
D1753.2  ; CH2_A.T.OFF_Lamp
D1853.2  ; CH3_A.T.OFF_Lamp
D1953.2  ; CH4_A.T.OFF_Lamp
